# PROVISIONAL - NOT FOR LVS, TIMING SIGNOFF, FABRICATION OR TAPEOUT
# Synthetic pin placement derived from the Verilog header.
# North/south pins: met2 X grid 0.23 + N*0.46 um.
# West/east pins: met3 Y grid 0.34 + N*0.68 um.
# Analog pins: 1.30 um wide met3 access for matching-or-wider NDR.
# Supply pins: distributed met3 access copied from the released X1 GDS.
# OBS geometry: copied from the matching released X1 LEF.
VERSION 5.7 ;
BUSBITCHARS "[]" ;
DIVIDERCHAR "/" ;
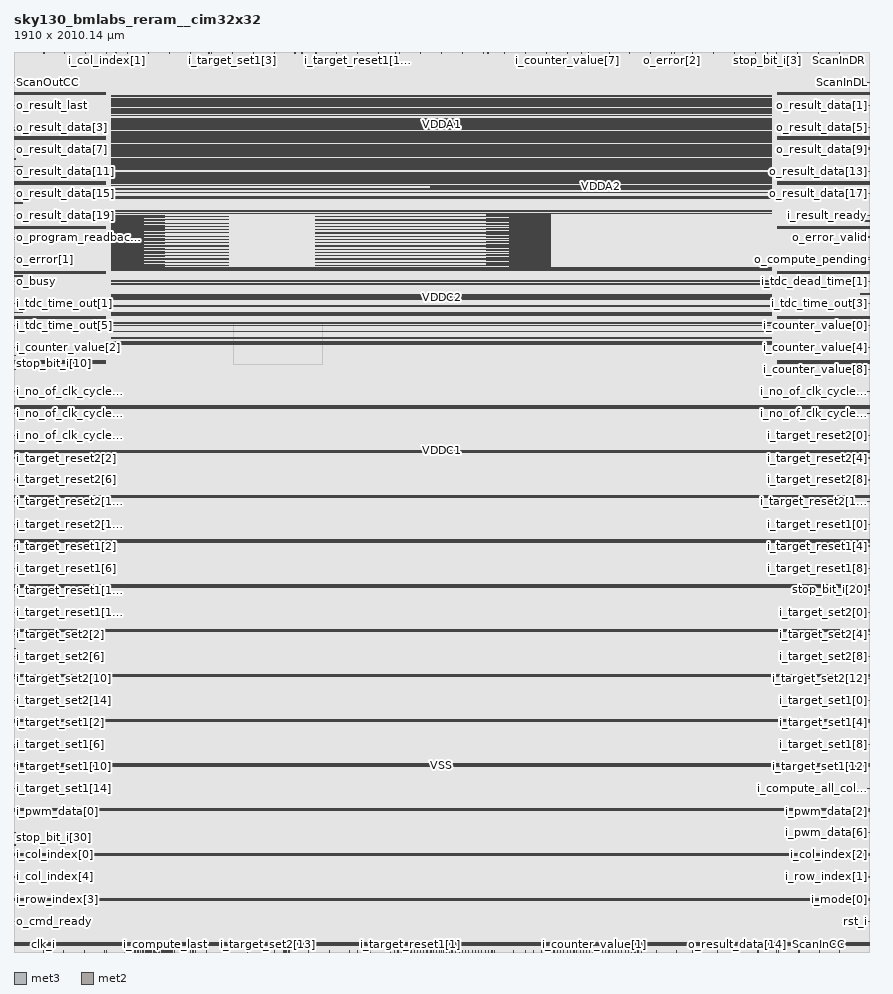
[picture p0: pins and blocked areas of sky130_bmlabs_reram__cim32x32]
MACRO sky130_bmlabs_reram__cim32x32
  CLASS BLOCK ;
  ORIGIN 0 0 ;
  FOREIGN sky130_bmlabs_reram__cim32x32 0 0 ;
  SIZE 1910 BY 2010.14 ;
  PIN VDDC1
    DIRECTION INOUT ;
    USE POWER ;
    PORT
      LAYER met3 ;
        RECT 1705 1318.6 1910 1320.4 ;
    END
    PORT
      LAYER met3 ;
        RECT 1705 1418.6 1910 1420.4 ;
    END
    PORT
      LAYER met3 ;
        RECT 1705 1518.6 1910 1520.4 ;
    END
    PORT
      LAYER met3 ;
        RECT 1705 1618.6 1910 1620.4 ;
    END
    PORT
      LAYER met3 ;
        RECT 1705 1718.6 1910 1720.4 ;
    END
    PORT
      LAYER met3 ;
        RECT 1705 1818.6 1910 1820.4 ;
    END
    PORT
      LAYER met3 ;
        RECT 1705 1918.6 1910 1920.4 ;
    END
    PORT
      LAYER met3 ;
        RECT 0 1718.6 205 1720.4 ;
    END
    PORT
      LAYER met3 ;
        RECT 0 1818.6 205 1820.4 ;
    END
    PORT
      LAYER met3 ;
        RECT 0 1918.6 205 1920.4 ;
    END
    PORT
      LAYER met3 ;
        RECT 0 1518.6 205 1520.4 ;
    END
    PORT
      LAYER met3 ;
        RECT 0 1618.6 205 1620.4 ;
    END
    PORT
      LAYER met3 ;
        RECT 0 1118.6 1910 1120.4 ;
    END
    PORT
      LAYER met3 ;
        RECT 0 1218.6 1910 1220.4 ;
    END
    PORT
      LAYER met3 ;
        RECT 0 1318.6 205 1320.4 ;
    END
    PORT
      LAYER met3 ;
        RECT 0 1018.6 1910 1020.4 ;
    END
    PORT
      LAYER met3 ;
        RECT 0 1418.6 205 1420.4 ;
    END
    PORT
      LAYER met3 ;
        RECT 0 718.6 1910 720.4 ;
    END
    PORT
      LAYER met3 ;
        RECT 0 818.6 1910 820.4 ;
    END
    PORT
      LAYER met3 ;
        RECT 0 418.6 1910 420.4 ;
    END
    PORT
      LAYER met3 ;
        RECT 0 918.6 1910 920.4 ;
    END
    PORT
      LAYER met3 ;
        RECT 0 318.6 1910 320.4 ;
    END
    PORT
      LAYER met3 ;
        RECT 0 18.6 1910 20.4 ;
    END
    PORT
      LAYER met3 ;
        RECT 0 118.6 1910 120.4 ;
    END
    PORT
      LAYER met3 ;
        RECT 0 218.6 1910 220.4 ;
    END
    PORT
      LAYER met3 ;
        RECT 0 518.6 1910 520.4 ;
    END
    PORT
      LAYER met3 ;
        RECT 0 618.6 1910 620.4 ;
    END
  END VDDC1
  PIN VDDC2
    DIRECTION INOUT ;
    USE POWER ;
    PORT
      LAYER met3 ;
        RECT 1107.355 1541.61 1198.805 1541.95 ;
    END
    PORT
      LAYER met3 ;
        RECT 1107.355 1538.89 1198.805 1539.23 ;
    END
    PORT
      LAYER met3 ;
        RECT 1107.355 1534.33 1198.805 1534.67 ;
    END
    PORT
      LAYER met3 ;
        RECT 1107.355 1531.61 1198.805 1531.95 ;
    END
    PORT
      LAYER met3 ;
        RECT 1107.355 1556.17 1198.805 1556.51 ;
    END
    PORT
      LAYER met3 ;
        RECT 1107.355 1553.45 1198.805 1553.79 ;
    END
    PORT
      LAYER met3 ;
        RECT 1107.355 1548.89 1198.805 1549.23 ;
    END
    PORT
      LAYER met3 ;
        RECT 1107.355 1546.17 1198.805 1546.51 ;
    END
    PORT
      LAYER met3 ;
        RECT 1107.355 1570.73 1198.805 1571.07 ;
    END
    PORT
      LAYER met3 ;
        RECT 1107.355 1568.01 1198.805 1568.35 ;
    END
    PORT
      LAYER met3 ;
        RECT 1107.355 1563.45 1198.805 1563.79 ;
    END
    PORT
      LAYER met3 ;
        RECT 1107.355 1560.73 1198.805 1561.07 ;
    END
    PORT
      LAYER met3 ;
        RECT 1107.355 1585.29 1198.805 1585.63 ;
    END
    PORT
      LAYER met3 ;
        RECT 1107.355 1582.57 1198.805 1582.91 ;
    END
    PORT
      LAYER met3 ;
        RECT 1107.355 1578.01 1198.805 1578.35 ;
    END
    PORT
      LAYER met3 ;
        RECT 1107.355 1575.29 1198.805 1575.63 ;
    END
    PORT
      LAYER met3 ;
        RECT 1107.355 1599.85 1198.805 1600.19 ;
    END
    PORT
      LAYER met3 ;
        RECT 1107.355 1597.13 1198.805 1597.47 ;
    END
    PORT
      LAYER met3 ;
        RECT 1107.355 1592.57 1198.805 1592.91 ;
    END
    PORT
      LAYER met3 ;
        RECT 1107.355 1589.85 1198.805 1590.19 ;
    END
    PORT
      LAYER met3 ;
        RECT 1107.355 1614.41 1198.805 1614.75 ;
    END
    PORT
      LAYER met3 ;
        RECT 1107.355 1611.69 1198.805 1612.03 ;
    END
    PORT
      LAYER met3 ;
        RECT 1107.355 1607.13 1198.805 1607.47 ;
    END
    PORT
      LAYER met3 ;
        RECT 1107.355 1604.41 1198.805 1604.75 ;
    END
    PORT
      LAYER met3 ;
        RECT 1107.355 1628.97 1198.805 1629.31 ;
    END
    PORT
      LAYER met3 ;
        RECT 1107.355 1626.25 1198.805 1626.59 ;
    END
    PORT
      LAYER met3 ;
        RECT 1107.355 1621.69 1198.805 1622.03 ;
    END
    PORT
      LAYER met3 ;
        RECT 1107.355 1618.97 1198.805 1619.31 ;
    END
    PORT
      LAYER met3 ;
        RECT 1107.355 1636.25 1198.805 1636.59 ;
    END
    PORT
      LAYER met3 ;
        RECT 1107.355 1640.81 1198.805 1641.15 ;
    END
    PORT
      LAYER met3 ;
        RECT 1107.355 1633.53 1198.805 1633.87 ;
    END
    PORT
      LAYER met3 ;
        RECT 1107.355 1643.53 1198.805 1643.87 ;
    END
    PORT
      LAYER met3 ;
        RECT 216.895 1905.7 1692.84 1906.7 ;
    END
    PORT
      LAYER met3 ;
        RECT 216.895 1903.7 1692.84 1904.7 ;
    END
    PORT
      LAYER met3 ;
        RECT 216.895 1899.7 1692.84 1900.7 ;
    END
    PORT
      LAYER met3 ;
        RECT 216.895 1910.255 1692.84 1911.255 ;
    END
    PORT
      LAYER met3 ;
        RECT 216.99 1639.315 288.37 1639.655 ;
    END
    PORT
      LAYER met3 ;
        RECT 216.99 1632.035 288.37 1632.375 ;
    END
    PORT
      LAYER met3 ;
        RECT 216.99 1551.955 288.37 1552.295 ;
    END
    PORT
      LAYER met3 ;
        RECT 216.99 1550.675 288.37 1551.015 ;
    END
    PORT
      LAYER met3 ;
        RECT 216.99 1543.395 288.37 1543.735 ;
    END
    PORT
      LAYER met3 ;
        RECT 216.99 1565.235 288.37 1565.575 ;
    END
    PORT
      LAYER met3 ;
        RECT 216.99 1587.075 288.37 1587.415 ;
    END
    PORT
      LAYER met3 ;
        RECT 216.99 1460.105 1692.935 1461.605 ;
    END
    PORT
      LAYER met3 ;
        RECT 216.99 1468.13 1692.935 1469.63 ;
    END
    PORT
      LAYER met3 ;
        RECT 216.99 1573.795 288.37 1574.135 ;
    END
    PORT
      LAYER met3 ;
        RECT 216.99 1581.075 288.37 1581.415 ;
    END
    PORT
      LAYER met3 ;
        RECT 216.99 1579.795 288.37 1580.135 ;
    END
    PORT
      LAYER met3 ;
        RECT 216.99 1530.115 288.37 1530.455 ;
    END
    PORT
      LAYER met3 ;
        RECT 216.99 1645.315 288.37 1645.655 ;
    END
    PORT
      LAYER met3 ;
        RECT 216.99 1463.105 1692.935 1464.605 ;
    END
    PORT
      LAYER met3 ;
        RECT 216.99 1523.695 1692.935 1524.695 ;
    END
    PORT
      LAYER met3 ;
        RECT 216.99 1537.395 288.37 1537.735 ;
    END
    PORT
      LAYER met3 ;
        RECT 216.99 1536.115 288.37 1536.455 ;
    END
    PORT
      LAYER met3 ;
        RECT 216.99 1557.955 288.37 1558.295 ;
    END
    PORT
      LAYER met3 ;
        RECT 216.99 1544.675 288.37 1545.015 ;
    END
    PORT
      LAYER met3 ;
        RECT 216.99 1601.635 288.37 1601.975 ;
    END
    PORT
      LAYER met3 ;
        RECT 216.99 1588.355 288.37 1588.695 ;
    END
    PORT
      LAYER met3 ;
        RECT 216.99 1595.635 288.37 1595.975 ;
    END
    PORT
      LAYER met3 ;
        RECT 216.99 1594.355 288.37 1594.695 ;
    END
    PORT
      LAYER met3 ;
        RECT 216.99 1616.195 288.37 1616.535 ;
    END
    PORT
      LAYER met3 ;
        RECT 216.99 1602.915 288.37 1603.255 ;
    END
    PORT
      LAYER met3 ;
        RECT 216.99 1610.195 288.37 1610.535 ;
    END
    PORT
      LAYER met3 ;
        RECT 216.99 1608.915 288.37 1609.255 ;
    END
    PORT
      LAYER met3 ;
        RECT 216.99 1630.755 288.37 1631.095 ;
    END
    PORT
      LAYER met3 ;
        RECT 216.99 1617.475 288.37 1617.815 ;
    END
    PORT
      LAYER met3 ;
        RECT 216.99 1624.755 288.37 1625.095 ;
    END
    PORT
      LAYER met3 ;
        RECT 216.99 1559.235 288.37 1559.575 ;
    END
    PORT
      LAYER met3 ;
        RECT 216.99 1623.475 288.37 1623.815 ;
    END
    PORT
      LAYER met3 ;
        RECT 216.99 1638.035 288.37 1638.375 ;
    END
    PORT
      LAYER met3 ;
        RECT 216.99 1572.515 288.37 1572.855 ;
    END
    PORT
      LAYER met3 ;
        RECT 216.99 1566.515 288.37 1566.855 ;
    END
    PORT
      LAYER met3 ;
        RECT 216.99 1398.62 1692.935 1399.62 ;
    END
    PORT
      LAYER met3 ;
        RECT 216.99 1385.695 1692.935 1386.695 ;
    END
    PORT
      LAYER met3 ;
        RECT 216.99 1362.35 1692.935 1363.85 ;
    END
    PORT
      LAYER met3 ;
        RECT 216.99 1404.27 1692.935 1405.27 ;
    END
    PORT
      LAYER met3 ;
        RECT 216.99 1426.895 1692.935 1428.395 ;
    END
    PORT
      LAYER met3 ;
        RECT 216.99 1424.145 1692.935 1425.645 ;
    END
  END VDDC2
  PIN VDDA1
    DIRECTION INOUT ;
    USE POWER ;
    PORT
      LAYER met3 ;
        RECT 1056.405 1529.33 1198.805 1529.67 ;
    END
    PORT
      LAYER met3 ;
        RECT 1056.405 1536.61 1198.805 1536.95 ;
    END
    PORT
      LAYER met3 ;
        RECT 1056.405 1543.89 1198.805 1544.23 ;
    END
    PORT
      LAYER met3 ;
        RECT 1056.405 1551.17 1198.805 1551.51 ;
    END
    PORT
      LAYER met3 ;
        RECT 1056.405 1558.45 1198.805 1558.79 ;
    END
    PORT
      LAYER met3 ;
        RECT 1056.405 1565.73 1198.805 1566.07 ;
    END
    PORT
      LAYER met3 ;
        RECT 1056.405 1573.01 1198.805 1573.35 ;
    END
    PORT
      LAYER met3 ;
        RECT 1056.405 1580.29 1198.805 1580.63 ;
    END
    PORT
      LAYER met3 ;
        RECT 1056.405 1587.57 1198.805 1587.91 ;
    END
    PORT
      LAYER met3 ;
        RECT 1056.405 1594.85 1198.805 1595.19 ;
    END
    PORT
      LAYER met3 ;
        RECT 1056.405 1602.13 1198.805 1602.47 ;
    END
    PORT
      LAYER met3 ;
        RECT 1056.405 1609.41 1198.805 1609.75 ;
    END
    PORT
      LAYER met3 ;
        RECT 1056.405 1616.69 1198.805 1617.03 ;
    END
    PORT
      LAYER met3 ;
        RECT 1056.405 1623.97 1198.805 1624.31 ;
    END
    PORT
      LAYER met3 ;
        RECT 1056.405 1638.53 1198.805 1638.87 ;
    END
    PORT
      LAYER met3 ;
        RECT 1056.405 1631.25 1198.805 1631.59 ;
    END
    PORT
      LAYER met3 ;
        RECT 1056.405 1645.81 1198.805 1646.15 ;
    END
    PORT
      LAYER met3 ;
        RECT 216.895 1848.475 1692.84 1849.475 ;
    END
    PORT
      LAYER met3 ;
        RECT 216.895 1812.94 1692.84 1813.94 ;
    END
    PORT
      LAYER met3 ;
        RECT 216.895 1783.685 1692.84 1784.685 ;
    END
    PORT
      LAYER met3 ;
        RECT 216.895 1755.265 1692.84 1756.265 ;
    END
    PORT
      LAYER met3 ;
        RECT 216.895 1723 1692.84 1724 ;
    END
    PORT
      LAYER met3 ;
        RECT 216.895 1729 1692.84 1730 ;
    END
    PORT
      LAYER met3 ;
        RECT 216.895 1703.22 1692.84 1704.22 ;
    END
    PORT
      LAYER met3 ;
        RECT 216.895 1695.22 1692.84 1696.22 ;
    END
    PORT
      LAYER met3 ;
        RECT 216.895 1687.22 1692.84 1688.22 ;
    END
    PORT
      LAYER met3 ;
        RECT 216.895 1872.1 1692.84 1873.1 ;
    END
    PORT
      LAYER met3 ;
        RECT 216.895 1874.1 1692.84 1875.1 ;
    END
    PORT
      LAYER met3 ;
        RECT 216.895 1876.1 1692.84 1877.1 ;
    END
    PORT
      LAYER met3 ;
        RECT 216.895 1878.1 1692.84 1879.1 ;
    END
    PORT
      LAYER met3 ;
        RECT 216.895 1880.1 1692.84 1881.1 ;
    END
    PORT
      LAYER met3 ;
        RECT 216.895 1711.22 1692.84 1712.22 ;
    END
    PORT
      LAYER met3 ;
        RECT 216.895 1735 1692.84 1736 ;
    END
    PORT
      LAYER met3 ;
        RECT 216.895 1741 1692.84 1742 ;
    END
    PORT
      LAYER met3 ;
        RECT 216.895 1767.265 1692.84 1768.265 ;
    END
    PORT
      LAYER met3 ;
        RECT 216.895 1795.685 1692.84 1796.685 ;
    END
    PORT
      LAYER met3 ;
        RECT 216.895 1824.94 1692.84 1825.94 ;
    END
    PORT
      LAYER met3 ;
        RECT 216.895 1685.36 1692.84 1686.36 ;
    END
    PORT
      LAYER met3 ;
        RECT 216.895 1860.475 1692.84 1861.475 ;
    END
    PORT
      LAYER met3 ;
        RECT 216.895 1882.1 1692.84 1883.1 ;
    END
    PORT
      LAYER met3 ;
        RECT 216.99 1633.675 336.095 1634.015 ;
    END
    PORT
      LAYER met3 ;
        RECT 216.99 1553.595 336.095 1553.935 ;
    END
    PORT
      LAYER met3 ;
        RECT 216.99 1549.035 336.095 1549.375 ;
    END
    PORT
      LAYER met3 ;
        RECT 216.99 1556.315 336.095 1556.655 ;
    END
    PORT
      LAYER met3 ;
        RECT 216.99 1570.875 336.095 1571.215 ;
    END
    PORT
      LAYER met3 ;
        RECT 216.99 1643.675 336.095 1644.015 ;
    END
    PORT
      LAYER met3 ;
        RECT 216.99 1575.435 336.095 1575.775 ;
    END
    PORT
      LAYER met3 ;
        RECT 216.99 1582.715 336.095 1583.055 ;
    END
    PORT
      LAYER met3 ;
        RECT 216.99 1525.295 1692.935 1526.295 ;
    END
    PORT
      LAYER met3 ;
        RECT 216.895 1653.885 1692.84 1654.885 ;
    END
    PORT
      LAYER met3 ;
        RECT 216.99 1578.155 336.095 1578.495 ;
    END
    PORT
      LAYER met3 ;
        RECT 216.99 1585.435 336.095 1585.775 ;
    END
    PORT
      LAYER met3 ;
        RECT 216.99 1531.755 336.095 1532.095 ;
    END
    PORT
      LAYER met3 ;
        RECT 216.99 1539.035 336.095 1539.375 ;
    END
    PORT
      LAYER met3 ;
        RECT 216.99 1534.475 336.095 1534.815 ;
    END
    PORT
      LAYER met3 ;
        RECT 216.99 1541.755 336.095 1542.095 ;
    END
    PORT
      LAYER met3 ;
        RECT 216.99 1546.315 336.095 1546.655 ;
    END
    PORT
      LAYER met3 ;
        RECT 216.99 1589.995 336.095 1590.335 ;
    END
    PORT
      LAYER met3 ;
        RECT 216.99 1597.275 336.095 1597.615 ;
    END
    PORT
      LAYER met3 ;
        RECT 216.99 1592.715 336.095 1593.055 ;
    END
    PORT
      LAYER met3 ;
        RECT 216.99 1599.995 336.095 1600.335 ;
    END
    PORT
      LAYER met3 ;
        RECT 216.99 1604.555 336.095 1604.895 ;
    END
    PORT
      LAYER met3 ;
        RECT 216.99 1611.835 336.095 1612.175 ;
    END
    PORT
      LAYER met3 ;
        RECT 216.99 1607.275 336.095 1607.615 ;
    END
    PORT
      LAYER met3 ;
        RECT 216.99 1614.555 336.095 1614.895 ;
    END
    PORT
      LAYER met3 ;
        RECT 216.99 1619.115 336.095 1619.455 ;
    END
    PORT
      LAYER met3 ;
        RECT 216.99 1626.395 336.095 1626.735 ;
    END
    PORT
      LAYER met3 ;
        RECT 216.99 1621.835 336.095 1622.175 ;
    END
    PORT
      LAYER met3 ;
        RECT 216.99 1629.115 336.095 1629.455 ;
    END
    PORT
      LAYER met3 ;
        RECT 216.99 1560.875 336.095 1561.215 ;
    END
    PORT
      LAYER met3 ;
        RECT 216.99 1636.395 336.095 1636.735 ;
    END
    PORT
      LAYER met3 ;
        RECT 216.99 1640.955 336.095 1641.295 ;
    END
    PORT
      LAYER met3 ;
        RECT 216.99 1568.155 336.095 1568.495 ;
    END
    PORT
      LAYER met3 ;
        RECT 216.99 1563.595 336.095 1563.935 ;
    END
  END VDDA1
  PIN VDDA2
    DIRECTION INOUT ;
    USE POWER ;
    PORT
      LAYER met3 ;
        RECT 929.635 1709.36 1692.84 1710.36 ;
    END
    PORT
      LAYER met3 ;
        RECT 929.635 1707.36 1692.84 1708.36 ;
    END
    PORT
      LAYER met3 ;
        RECT 929.635 1705.36 1692.84 1706.36 ;
    END
  END VDDA2
  PIN VSS
    DIRECTION INOUT ;
    USE GROUND ;
    PORT
      LAYER met3 ;
        RECT 673.905 1532.97 1198.805 1533.31 ;
    END
    PORT
      LAYER met3 ;
        RECT 673.905 1540.25 1198.805 1540.59 ;
    END
    PORT
      LAYER met3 ;
        RECT 673.905 1547.53 1198.805 1547.87 ;
    END
    PORT
      LAYER met3 ;
        RECT 673.905 1554.81 1198.805 1555.15 ;
    END
    PORT
      LAYER met3 ;
        RECT 673.905 1562.09 1198.805 1562.43 ;
    END
    PORT
      LAYER met3 ;
        RECT 673.905 1569.37 1198.805 1569.71 ;
    END
    PORT
      LAYER met3 ;
        RECT 673.905 1576.65 1198.805 1576.99 ;
    END
    PORT
      LAYER met3 ;
        RECT 673.905 1583.93 1198.805 1584.27 ;
    END
    PORT
      LAYER met3 ;
        RECT 673.905 1591.21 1198.805 1591.55 ;
    END
    PORT
      LAYER met3 ;
        RECT 673.905 1598.49 1198.805 1598.83 ;
    END
    PORT
      LAYER met3 ;
        RECT 673.905 1605.77 1198.805 1606.11 ;
    END
    PORT
      LAYER met3 ;
        RECT 673.905 1613.05 1198.805 1613.39 ;
    END
    PORT
      LAYER met3 ;
        RECT 673.905 1620.33 1198.805 1620.67 ;
    END
    PORT
      LAYER met3 ;
        RECT 673.905 1627.61 1198.805 1627.95 ;
    END
    PORT
      LAYER met3 ;
        RECT 673.905 1634.89 1198.805 1635.23 ;
    END
    PORT
      LAYER met3 ;
        RECT 673.905 1642.17 1198.805 1642.51 ;
    END
    PORT
      LAYER met3 ;
        RECT 1705 1315 1910 1316.8 ;
    END
    PORT
      LAYER met3 ;
        RECT 1705 1415 1910 1416.8 ;
    END
    PORT
      LAYER met3 ;
        RECT 1705 1515 1910 1516.8 ;
    END
    PORT
      LAYER met3 ;
        RECT 1705 1615 1910 1616.8 ;
    END
    PORT
      LAYER met3 ;
        RECT 1705 1715 1910 1716.8 ;
    END
    PORT
      LAYER met3 ;
        RECT 1705 1815 1910 1816.8 ;
    END
    PORT
      LAYER met3 ;
        RECT 1705 1915 1910 1916.8 ;
    END
    PORT
      LAYER met3 ;
        RECT 216.895 1838.475 1692.84 1839.475 ;
    END
    PORT
      LAYER met3 ;
        RECT 216.895 1840.475 1692.84 1841.475 ;
    END
    PORT
      LAYER met3 ;
        RECT 216.895 1842.475 1692.84 1843.475 ;
    END
    PORT
      LAYER met3 ;
        RECT 216.895 1844.475 1692.84 1845.475 ;
    END
    PORT
      LAYER met3 ;
        RECT 216.895 1846.475 1692.84 1847.475 ;
    END
    PORT
      LAYER met3 ;
        RECT 216.895 1836.475 1692.84 1837.475 ;
    END
    PORT
      LAYER met3 ;
        RECT 216.895 1808.94 1692.84 1809.94 ;
    END
    PORT
      LAYER met3 ;
        RECT 216.895 1810.94 1692.84 1811.94 ;
    END
    PORT
      LAYER met3 ;
        RECT 216.895 1814.94 1692.84 1815.94 ;
    END
    PORT
      LAYER met3 ;
        RECT 216.895 1816.94 1692.84 1817.94 ;
    END
    PORT
      LAYER met3 ;
        RECT 216.895 1818.94 1692.84 1819.94 ;
    END
    PORT
      LAYER met3 ;
        RECT 216.895 1806.94 1692.84 1807.94 ;
    END
    PORT
      LAYER met3 ;
        RECT 216.895 1779.685 1692.84 1780.685 ;
    END
    PORT
      LAYER met3 ;
        RECT 216.895 1781.685 1692.84 1782.685 ;
    END
    PORT
      LAYER met3 ;
        RECT 216.895 1785.685 1692.84 1786.685 ;
    END
    PORT
      LAYER met3 ;
        RECT 216.895 1787.685 1692.84 1788.685 ;
    END
    PORT
      LAYER met3 ;
        RECT 216.895 1789.685 1692.84 1790.685 ;
    END
    PORT
      LAYER met3 ;
        RECT 216.895 1777.685 1692.84 1778.685 ;
    END
    PORT
      LAYER met3 ;
        RECT 216.895 1749.265 1692.84 1750.265 ;
    END
    PORT
      LAYER met3 ;
        RECT 216.895 1751.265 1692.84 1752.265 ;
    END
    PORT
      LAYER met3 ;
        RECT 216.895 1753.265 1692.84 1754.265 ;
    END
    PORT
      LAYER met3 ;
        RECT 216.895 1757.265 1692.84 1758.265 ;
    END
    PORT
      LAYER met3 ;
        RECT 216.895 1759.265 1692.84 1760.265 ;
    END
    PORT
      LAYER met3 ;
        RECT 216.895 1747.265 1692.84 1748.265 ;
    END
    PORT
      LAYER met3 ;
        RECT 216.895 1719 1692.84 1720 ;
    END
    PORT
      LAYER met3 ;
        RECT 216.895 1721 1692.84 1722 ;
    END
    PORT
      LAYER met3 ;
        RECT 216.895 1725 1692.84 1726 ;
    END
    PORT
      LAYER met3 ;
        RECT 216.895 1727 1692.84 1728 ;
    END
    PORT
      LAYER met3 ;
        RECT 216.895 1717 1692.84 1718 ;
    END
    PORT
      LAYER met3 ;
        RECT 216.895 1683.5 1692.84 1684.5 ;
    END
    PORT
      LAYER met3 ;
        RECT 216.895 1912.515 1692.84 1913.515 ;
    END
    PORT
      LAYER met3 ;
        RECT 216.895 1737 1692.84 1738 ;
    END
    PORT
      LAYER met3 ;
        RECT 216.895 1739 1692.84 1740 ;
    END
    PORT
      LAYER met3 ;
        RECT 216.895 1731 1692.84 1732 ;
    END
    PORT
      LAYER met3 ;
        RECT 216.895 1733 1692.84 1734 ;
    END
    PORT
      LAYER met3 ;
        RECT 216.895 1761.265 1692.84 1762.265 ;
    END
    PORT
      LAYER met3 ;
        RECT 216.895 1763.265 1692.84 1764.265 ;
    END
    PORT
      LAYER met3 ;
        RECT 216.895 1765.265 1692.84 1766.265 ;
    END
    PORT
      LAYER met3 ;
        RECT 216.895 1769.265 1692.84 1770.265 ;
    END
    PORT
      LAYER met3 ;
        RECT 216.895 1771.265 1692.84 1772.265 ;
    END
    PORT
      LAYER met3 ;
        RECT 216.895 1791.685 1692.84 1792.685 ;
    END
    PORT
      LAYER met3 ;
        RECT 216.895 1793.685 1692.84 1794.685 ;
    END
    PORT
      LAYER met3 ;
        RECT 216.895 1797.685 1692.84 1798.685 ;
    END
    PORT
      LAYER met3 ;
        RECT 216.895 1799.685 1692.84 1800.685 ;
    END
    PORT
      LAYER met3 ;
        RECT 216.895 1801.685 1692.84 1802.685 ;
    END
    PORT
      LAYER met3 ;
        RECT 216.895 1820.94 1692.84 1821.94 ;
    END
    PORT
      LAYER met3 ;
        RECT 216.895 1822.94 1692.84 1823.94 ;
    END
    PORT
      LAYER met3 ;
        RECT 216.895 1826.94 1692.84 1827.94 ;
    END
    PORT
      LAYER met3 ;
        RECT 216.895 1828.94 1692.84 1829.94 ;
    END
    PORT
      LAYER met3 ;
        RECT 216.895 1830.94 1692.84 1831.94 ;
    END
    PORT
      LAYER met3 ;
        RECT 216.895 1850.475 1692.84 1851.475 ;
    END
    PORT
      LAYER met3 ;
        RECT 216.895 1852.475 1692.84 1853.475 ;
    END
    PORT
      LAYER met3 ;
        RECT 216.895 1854.475 1692.84 1855.475 ;
    END
    PORT
      LAYER met3 ;
        RECT 216.895 1856.475 1692.84 1857.475 ;
    END
    PORT
      LAYER met3 ;
        RECT 216.895 1858.475 1692.84 1859.475 ;
    END
    PORT
      LAYER met3 ;
        RECT 216.895 1868.02 1692.84 1869.02 ;
    END
    PORT
      LAYER met3 ;
        RECT 216.895 1887.335 1692.84 1888.335 ;
    END
    PORT
      LAYER met3 ;
        RECT 216.895 1889.335 1692.84 1890.335 ;
    END
    PORT
      LAYER met3 ;
        RECT 216.895 1891.335 1692.84 1892.335 ;
    END
    PORT
      LAYER met3 ;
        RECT 216.895 1893.335 1692.84 1894.335 ;
    END
    PORT
      LAYER met3 ;
        RECT 216.895 1897.7 1692.84 1898.7 ;
    END
    PORT
      LAYER met3 ;
        RECT 216.895 1901.7 1692.84 1902.7 ;
    END
    PORT
      LAYER met3 ;
        RECT 0 1915 205 1916.8 ;
    END
    PORT
      LAYER met3 ;
        RECT 0 1715 205 1716.8 ;
    END
    PORT
      LAYER met3 ;
        RECT 0 1815 205 1816.8 ;
    END
    PORT
      LAYER met3 ;
        RECT 0 1515 205 1516.8 ;
    END
    PORT
      LAYER met3 ;
        RECT 0 1615 205 1616.8 ;
    END
    PORT
      LAYER met3 ;
        RECT 216.99 1635.035 478.585 1635.375 ;
    END
    PORT
      LAYER met3 ;
        RECT 216.99 1547.675 478.585 1548.015 ;
    END
    PORT
      LAYER met3 ;
        RECT 216.99 1540.395 478.585 1540.735 ;
    END
    PORT
      LAYER met3 ;
        RECT 216.99 1584.075 478.585 1584.415 ;
    END
    PORT
      LAYER met3 ;
        RECT 216.99 1465.725 1692.935 1467.225 ;
    END
    PORT
      LAYER met3 ;
        RECT 216.99 1576.795 478.585 1577.135 ;
    END
    PORT
      LAYER met3 ;
        RECT 216.99 1649.175 1692.935 1650.175 ;
    END
    PORT
      LAYER met3 ;
        RECT 216.99 1526.75 1692.935 1527.75 ;
    END
    PORT
      LAYER met3 ;
        RECT 216.99 1598.635 478.585 1598.975 ;
    END
    PORT
      LAYER met3 ;
        RECT 216.99 1457.28 1692.935 1458.78 ;
    END
    PORT
      LAYER met3 ;
        RECT 216.99 1642.315 478.585 1642.655 ;
    END
    PORT
      LAYER met3 ;
        RECT 216.99 1533.115 478.585 1533.455 ;
    END
    PORT
      LAYER met3 ;
        RECT 216.99 1490.735 1692.935 1492.235 ;
    END
    PORT
      LAYER met3 ;
        RECT 216.99 1497.995 1692.935 1499.495 ;
    END
    PORT
      LAYER met3 ;
        RECT 216.99 1521.18 1692.935 1522.18 ;
    END
    PORT
      LAYER met3 ;
        RECT 216.895 1655.425 1692.84 1656.425 ;
    END
    PORT
      LAYER met3 ;
        RECT 216.99 1554.955 478.585 1555.295 ;
    END
    PORT
      LAYER met3 ;
        RECT 216.99 1591.355 478.585 1591.695 ;
    END
    PORT
      LAYER met3 ;
        RECT 216.99 1613.195 478.585 1613.535 ;
    END
    PORT
      LAYER met3 ;
        RECT 216.99 1605.915 478.585 1606.255 ;
    END
    PORT
      LAYER met3 ;
        RECT 216.99 1627.755 478.585 1628.095 ;
    END
    PORT
      LAYER met3 ;
        RECT 216.99 1620.475 478.585 1620.815 ;
    END
    PORT
      LAYER met3 ;
        RECT 216.99 1562.235 478.585 1562.575 ;
    END
    PORT
      LAYER met3 ;
        RECT 216.99 1569.515 478.585 1569.855 ;
    END
    PORT
      LAYER met3 ;
        RECT 0 1415 205 1416.8 ;
    END
    PORT
      LAYER met3 ;
        RECT 216.99 1441.55 1692.935 1443.05 ;
    END
    PORT
      LAYER met3 ;
        RECT 0 1115 1910 1116.8 ;
    END
    PORT
      LAYER met3 ;
        RECT 0 1215 1910 1216.8 ;
    END
    PORT
      LAYER met3 ;
        RECT 216.99 1357.08 1692.935 1358.58 ;
    END
    PORT
      LAYER met3 ;
        RECT 216.99 1371.215 1692.935 1372.715 ;
    END
    PORT
      LAYER met3 ;
        RECT 0 1315 205 1316.8 ;
    END
    PORT
      LAYER met3 ;
        RECT 0 1015 1910 1016.8 ;
    END
    PORT
      LAYER met3 ;
        RECT 216.99 1421.265 1692.935 1422.765 ;
    END
    PORT
      LAYER met3 ;
        RECT 0 715 1910 716.8 ;
    END
    PORT
      LAYER met3 ;
        RECT 0 815 1910 816.8 ;
    END
    PORT
      LAYER met3 ;
        RECT 0 415 1910 416.8 ;
    END
    PORT
      LAYER met3 ;
        RECT 0 915 1910 916.8 ;
    END
    PORT
      LAYER met3 ;
        RECT 0 315 1910 316.8 ;
    END
    PORT
      LAYER met3 ;
        RECT 0 15 1910 16.8 ;
    END
    PORT
      LAYER met3 ;
        RECT 0 115 1910 116.8 ;
    END
    PORT
      LAYER met3 ;
        RECT 0 215 1910 216.8 ;
    END
    PORT
      LAYER met3 ;
        RECT 0 515 1910 516.8 ;
    END
    PORT
      LAYER met3 ;
        RECT 0 615 1910 616.8 ;
    END
  END VSS
  PIN interface_sel
    DIRECTION INPUT ;
    USE SIGNAL ;
    PORT
      LAYER met2 ;
        RECT 207.08 0 207.38 2.91 ;
    END
  END interface_sel
  PIN i_Levelsh_enable
    DIRECTION INPUT ;
    USE SIGNAL ;
    PORT
      LAYER met3 ;
        RECT 1907.09 217.79 1910 218.09 ;
    END
  END i_Levelsh_enable
  PIN clk_i
    DIRECTION INPUT ;
    USE SIGNAL ;
    PORT
      LAYER met2 ;
        RECT 65.4 0 65.7 2.91 ;
    END
  END clk_i
  PIN rst_i
    DIRECTION INPUT ;
    USE SIGNAL ;
    PORT
      LAYER met3 ;
        RECT 1907.09 68.87 1910 69.17 ;
    END
  END rst_i
  PIN i_cmd_valid
    DIRECTION INPUT ;
    USE SIGNAL ;
    PORT
      LAYER met2 ;
        RECT 66.78 2007.23 67.08 2010.14 ;
    END
  END i_cmd_valid
  PIN o_cmd_ready
    DIRECTION OUTPUT ;
    USE SIGNAL ;
    PORT
      LAYER met3 ;
        RECT 0 68.87 2.91 69.17 ;
    END
  END o_cmd_ready
  PIN i_mode[1]
    DIRECTION INPUT ;
    USE SIGNAL ;
    PORT
      LAYER met2 ;
        RECT 110.94 0 111.24 2.91 ;
    END
  END i_mode[1]
  PIN i_mode[0]
    DIRECTION INPUT ;
    USE SIGNAL ;
    PORT
      LAYER met3 ;
        RECT 1907.09 117.83 1910 118.13 ;
    END
  END i_mode[0]
  PIN i_row_index[4]
    DIRECTION INPUT ;
    USE SIGNAL ;
    PORT
      LAYER met2 ;
        RECT 113.24 2007.23 113.54 2010.14 ;
    END
  END i_row_index[4]
  PIN i_row_index[3]
    DIRECTION INPUT ;
    USE SIGNAL ;
    PORT
      LAYER met3 ;
        RECT 0 117.83 2.91 118.13 ;
    END
  END i_row_index[3]
  PIN i_row_index[2]
    DIRECTION INPUT ;
    USE SIGNAL ;
    PORT
      LAYER met2 ;
        RECT 156.48 0 156.78 2.91 ;
    END
  END i_row_index[2]
  PIN i_row_index[1]
    DIRECTION INPUT ;
    USE SIGNAL ;
    PORT
      LAYER met3 ;
        RECT 1907.09 167.47 1910 167.77 ;
    END
  END i_row_index[1]
  PIN i_row_index[0]
    DIRECTION INPUT ;
    USE SIGNAL ;
    PORT
      LAYER met2 ;
        RECT 160.16 2007.23 160.46 2010.14 ;
    END
  END i_row_index[0]
  PIN i_col_index[4]
    DIRECTION INPUT ;
    USE SIGNAL ;
    PORT
      LAYER met3 ;
        RECT 0 167.47 2.91 167.77 ;
    END
  END i_col_index[4]
  PIN i_col_index[3]
    DIRECTION INPUT ;
    USE SIGNAL ;
    PORT
      LAYER met2 ;
        RECT 202.48 0 202.78 2.91 ;
    END
  END i_col_index[3]
  PIN i_col_index[2]
    DIRECTION INPUT ;
    USE SIGNAL ;
    PORT
      LAYER met3 ;
        RECT 1907.09 217.11 1910 217.41 ;
    END
  END i_col_index[2]
  PIN i_col_index[1]
    DIRECTION INPUT ;
    USE SIGNAL ;
    PORT
      LAYER met2 ;
        RECT 207.08 2007.23 207.38 2010.14 ;
    END
  END i_col_index[1]
  PIN i_col_index[0]
    DIRECTION INPUT ;
    USE SIGNAL ;
    PORT
      LAYER met3 ;
        RECT 0 217.11 2.91 217.41 ;
    END
  END i_col_index[0]
  PIN i_pwm_data[7]
    DIRECTION INPUT ;
    USE SIGNAL ;
    PORT
      LAYER met2 ;
        RECT 248.02 0 248.32 2.91 ;
    END
  END i_pwm_data[7]
  PIN i_pwm_data[6]
    DIRECTION INPUT ;
    USE SIGNAL ;
    PORT
      LAYER met3 ;
        RECT 1907.09 266.07 1910 266.37 ;
    END
  END i_pwm_data[6]
  PIN i_pwm_data[5]
    DIRECTION INPUT ;
    USE SIGNAL ;
    PORT
      LAYER met2 ;
        RECT 253.54 2007.23 253.84 2010.14 ;
    END
  END i_pwm_data[5]
  PIN i_pwm_data[4]
    DIRECTION INPUT ;
    USE SIGNAL ;
    PORT
      LAYER met3 ;
        RECT 0 266.07 2.91 266.37 ;
    END
  END i_pwm_data[4]
  PIN i_pwm_data[3]
    DIRECTION INPUT ;
    USE SIGNAL ;
    PORT
      LAYER met2 ;
        RECT 293.56 0 293.86 2.91 ;
    END
  END i_pwm_data[3]
  PIN i_pwm_data[2]
    DIRECTION INPUT ;
    USE SIGNAL ;
    PORT
      LAYER met3 ;
        RECT 1907.09 314.35 1910 314.65 ;
    END
  END i_pwm_data[2]
  PIN i_pwm_data[1]
    DIRECTION INPUT ;
    USE SIGNAL ;
    PORT
      LAYER met2 ;
        RECT 300.46 2007.23 300.76 2010.14 ;
    END
  END i_pwm_data[1]
  PIN i_pwm_data[0]
    DIRECTION INPUT ;
    USE SIGNAL ;
    PORT
      LAYER met3 ;
        RECT 0 314.35 2.91 314.65 ;
    END
  END i_pwm_data[0]
  PIN i_compute_last
    DIRECTION INPUT ;
    USE SIGNAL ;
    PORT
      LAYER met2 ;
        RECT 339.1 0 339.4 2.91 ;
    END
  END i_compute_last
  PIN i_compute_all_columns
    DIRECTION INPUT ;
    USE SIGNAL ;
    PORT
      LAYER met3 ;
        RECT 1907.09 364.67 1910 364.97 ;
    END
  END i_compute_all_columns
  PIN i_target_set1[15]
    DIRECTION INPUT ;
    USE SIGNAL ;
    PORT
      LAYER met2 ;
        RECT 346.92 2007.23 347.22 2010.14 ;
    END
  END i_target_set1[15]
  PIN i_target_set1[14]
    DIRECTION INPUT ;
    USE SIGNAL ;
    PORT
      LAYER met3 ;
        RECT 0 364.67 2.91 364.97 ;
    END
  END i_target_set1[14]
  PIN i_target_set1[13]
    DIRECTION INPUT ;
    USE SIGNAL ;
    PORT
      LAYER met2 ;
        RECT 384.64 0 384.94 2.91 ;
    END
  END i_target_set1[13]
  PIN i_target_set1[12]
    DIRECTION INPUT ;
    USE SIGNAL ;
    PORT
      LAYER met3 ;
        RECT 1907.09 413.63 1910 413.93 ;
    END
  END i_target_set1[12]
  PIN i_target_set1[11]
    DIRECTION INPUT ;
    USE SIGNAL ;
    PORT
      LAYER met2 ;
        RECT 393.84 2007.23 394.14 2010.14 ;
    END
  END i_target_set1[11]
  PIN i_target_set1[10]
    DIRECTION INPUT ;
    USE SIGNAL ;
    PORT
      LAYER met3 ;
        RECT 0 413.63 2.91 413.93 ;
    END
  END i_target_set1[10]
  PIN i_target_set1[9]
    DIRECTION INPUT ;
    USE SIGNAL ;
    PORT
      LAYER met2 ;
        RECT 430.18 0 430.48 2.91 ;
    END
  END i_target_set1[9]
  PIN i_target_set1[8]
    DIRECTION INPUT ;
    USE SIGNAL ;
    PORT
      LAYER met3 ;
        RECT 1907.09 463.27 1910 463.57 ;
    END
  END i_target_set1[8]
  PIN i_target_set1[7]
    DIRECTION INPUT ;
    USE SIGNAL ;
    PORT
      LAYER met2 ;
        RECT 440.76 2007.23 441.06 2010.14 ;
    END
  END i_target_set1[7]
  PIN i_target_set1[6]
    DIRECTION INPUT ;
    USE SIGNAL ;
    PORT
      LAYER met3 ;
        RECT 0 463.27 2.91 463.57 ;
    END
  END i_target_set1[6]
  PIN i_target_set1[5]
    DIRECTION INPUT ;
    USE SIGNAL ;
    PORT
      LAYER met2 ;
        RECT 475.72 0 476.02 2.91 ;
    END
  END i_target_set1[5]
  PIN i_target_set1[4]
    DIRECTION INPUT ;
    USE SIGNAL ;
    PORT
      LAYER met3 ;
        RECT 1907.09 512.23 1910 512.53 ;
    END
  END i_target_set1[4]
  PIN i_target_set1[3]
    DIRECTION INPUT ;
    USE SIGNAL ;
    PORT
      LAYER met2 ;
        RECT 487.22 2007.23 487.52 2010.14 ;
    END
  END i_target_set1[3]
  PIN i_target_set1[2]
    DIRECTION INPUT ;
    USE SIGNAL ;
    PORT
      LAYER met3 ;
        RECT 0 512.23 2.91 512.53 ;
    END
  END i_target_set1[2]
  PIN i_target_set1[1]
    DIRECTION INPUT ;
    USE SIGNAL ;
    PORT
      LAYER met2 ;
        RECT 521.72 0 522.02 2.91 ;
    END
  END i_target_set1[1]
  PIN i_target_set1[0]
    DIRECTION INPUT ;
    USE SIGNAL ;
    PORT
      LAYER met3 ;
        RECT 1907.09 561.87 1910 562.17 ;
    END
  END i_target_set1[0]
  PIN i_target_set2[15]
    DIRECTION INPUT ;
    USE SIGNAL ;
    PORT
      LAYER met2 ;
        RECT 534.14 2007.23 534.44 2010.14 ;
    END
  END i_target_set2[15]
  PIN i_target_set2[14]
    DIRECTION INPUT ;
    USE SIGNAL ;
    PORT
      LAYER met3 ;
        RECT 0 561.87 2.91 562.17 ;
    END
  END i_target_set2[14]
  PIN i_target_set2[13]
    DIRECTION INPUT ;
    USE SIGNAL ;
    PORT
      LAYER met2 ;
        RECT 567.26 0 567.56 2.91 ;
    END
  END i_target_set2[13]
  PIN i_target_set2[12]
    DIRECTION INPUT ;
    USE SIGNAL ;
    PORT
      LAYER met3 ;
        RECT 1907.09 610.83 1910 611.13 ;
    END
  END i_target_set2[12]
  PIN i_target_set2[11]
    DIRECTION INPUT ;
    USE SIGNAL ;
    PORT
      LAYER met2 ;
        RECT 581.06 2007.23 581.36 2010.14 ;
    END
  END i_target_set2[11]
  PIN i_target_set2[10]
    DIRECTION INPUT ;
    USE SIGNAL ;
    PORT
      LAYER met3 ;
        RECT 0 610.83 2.91 611.13 ;
    END
  END i_target_set2[10]
  PIN i_target_set2[9]
    DIRECTION INPUT ;
    USE SIGNAL ;
    PORT
      LAYER met2 ;
        RECT 612.8 0 613.1 2.91 ;
    END
  END i_target_set2[9]
  PIN i_target_set2[8]
    DIRECTION INPUT ;
    USE SIGNAL ;
    PORT
      LAYER met3 ;
        RECT 1907.09 660.47 1910 660.77 ;
    END
  END i_target_set2[8]
  PIN i_target_set2[7]
    DIRECTION INPUT ;
    USE SIGNAL ;
    PORT
      LAYER met2 ;
        RECT 627.52 2007.23 627.82 2010.14 ;
    END
  END i_target_set2[7]
  PIN i_target_set2[6]
    DIRECTION INPUT ;
    USE SIGNAL ;
    PORT
      LAYER met3 ;
        RECT 0 660.47 2.91 660.77 ;
    END
  END i_target_set2[6]
  PIN i_target_set2[5]
    DIRECTION INPUT ;
    USE SIGNAL ;
    PORT
      LAYER met2 ;
        RECT 658.34 0 658.64 2.91 ;
    END
  END i_target_set2[5]
  PIN i_target_set2[4]
    DIRECTION INPUT ;
    USE SIGNAL ;
    PORT
      LAYER met3 ;
        RECT 1907.09 709.43 1910 709.73 ;
    END
  END i_target_set2[4]
  PIN i_target_set2[3]
    DIRECTION INPUT ;
    USE SIGNAL ;
    PORT
      LAYER met2 ;
        RECT 674.44 2007.23 674.74 2010.14 ;
    END
  END i_target_set2[3]
  PIN i_target_set2[2]
    DIRECTION INPUT ;
    USE SIGNAL ;
    PORT
      LAYER met3 ;
        RECT 0 709.43 2.91 709.73 ;
    END
  END i_target_set2[2]
  PIN i_target_set2[1]
    DIRECTION INPUT ;
    USE SIGNAL ;
    PORT
      LAYER met2 ;
        RECT 703.88 0 704.18 2.91 ;
    END
  END i_target_set2[1]
  PIN i_target_set2[0]
    DIRECTION INPUT ;
    USE SIGNAL ;
    PORT
      LAYER met3 ;
        RECT 1907.09 758.39 1910 758.69 ;
    END
  END i_target_set2[0]
  PIN i_target_reset1[15]
    DIRECTION INPUT ;
    USE SIGNAL ;
    PORT
      LAYER met2 ;
        RECT 720.9 2007.23 721.2 2010.14 ;
    END
  END i_target_reset1[15]
  PIN i_target_reset1[14]
    DIRECTION INPUT ;
    USE SIGNAL ;
    PORT
      LAYER met3 ;
        RECT 0 758.39 2.91 758.69 ;
    END
  END i_target_reset1[14]
  PIN i_target_reset1[13]
    DIRECTION INPUT ;
    USE SIGNAL ;
    PORT
      LAYER met2 ;
        RECT 749.42 0 749.72 2.91 ;
    END
  END i_target_reset1[13]
  PIN i_target_reset1[12]
    DIRECTION INPUT ;
    USE SIGNAL ;
    PORT
      LAYER met3 ;
        RECT 1907.09 808.03 1910 808.33 ;
    END
  END i_target_reset1[12]
  PIN i_target_reset1[11]
    DIRECTION INPUT ;
    USE SIGNAL ;
    PORT
      LAYER met2 ;
        RECT 767.82 2007.23 768.12 2010.14 ;
    END
  END i_target_reset1[11]
  PIN i_target_reset1[10]
    DIRECTION INPUT ;
    USE SIGNAL ;
    PORT
      LAYER met3 ;
        RECT 0 808.03 2.91 808.33 ;
    END
  END i_target_reset1[10]
  PIN i_target_reset1[9]
    DIRECTION INPUT ;
    USE SIGNAL ;
    PORT
      LAYER met2 ;
        RECT 795.42 0 795.72 2.91 ;
    END
  END i_target_reset1[9]
  PIN i_target_reset1[8]
    DIRECTION INPUT ;
    USE SIGNAL ;
    PORT
      LAYER met3 ;
        RECT 1907.09 856.99 1910 857.29 ;
    END
  END i_target_reset1[8]
  PIN i_target_reset1[7]
    DIRECTION INPUT ;
    USE SIGNAL ;
    PORT
      LAYER met2 ;
        RECT 814.74 2007.23 815.04 2010.14 ;
    END
  END i_target_reset1[7]
  PIN i_target_reset1[6]
    DIRECTION INPUT ;
    USE SIGNAL ;
    PORT
      LAYER met3 ;
        RECT 0 856.99 2.91 857.29 ;
    END
  END i_target_reset1[6]
  PIN i_target_reset1[5]
    DIRECTION INPUT ;
    USE SIGNAL ;
    PORT
      LAYER met2 ;
        RECT 840.96 0 841.26 2.91 ;
    END
  END i_target_reset1[5]
  PIN i_target_reset1[4]
    DIRECTION INPUT ;
    USE SIGNAL ;
    PORT
      LAYER met3 ;
        RECT 1907.09 906.63 1910 906.93 ;
    END
  END i_target_reset1[4]
  PIN i_target_reset1[3]
    DIRECTION INPUT ;
    USE SIGNAL ;
    PORT
      LAYER met2 ;
        RECT 861.2 2007.23 861.5 2010.14 ;
    END
  END i_target_reset1[3]
  PIN i_target_reset1[2]
    DIRECTION INPUT ;
    USE SIGNAL ;
    PORT
      LAYER met3 ;
        RECT 0 906.63 2.91 906.93 ;
    END
  END i_target_reset1[2]
  PIN i_target_reset1[1]
    DIRECTION INPUT ;
    USE SIGNAL ;
    PORT
      LAYER met2 ;
        RECT 886.5 0 886.8 2.91 ;
    END
  END i_target_reset1[1]
  PIN i_target_reset1[0]
    DIRECTION INPUT ;
    USE SIGNAL ;
    PORT
      LAYER met3 ;
        RECT 1907.09 955.59 1910 955.89 ;
    END
  END i_target_reset1[0]
  PIN i_target_reset2[15]
    DIRECTION INPUT ;
    USE SIGNAL ;
    PORT
      LAYER met2 ;
        RECT 908.12 2007.23 908.42 2010.14 ;
    END
  END i_target_reset2[15]
  PIN i_target_reset2[14]
    DIRECTION INPUT ;
    USE SIGNAL ;
    PORT
      LAYER met3 ;
        RECT 0 955.59 2.91 955.89 ;
    END
  END i_target_reset2[14]
  PIN i_target_reset2[13]
    DIRECTION INPUT ;
    USE SIGNAL ;
    PORT
      LAYER met2 ;
        RECT 932.04 0 932.34 2.91 ;
    END
  END i_target_reset2[13]
  PIN i_target_reset2[12]
    DIRECTION INPUT ;
    USE SIGNAL ;
    PORT
      LAYER met3 ;
        RECT 1907.09 1005.23 1910 1005.53 ;
    END
  END i_target_reset2[12]
  PIN i_target_reset2[11]
    DIRECTION INPUT ;
    USE SIGNAL ;
    PORT
      LAYER met2 ;
        RECT 955.04 2007.23 955.34 2010.14 ;
    END
  END i_target_reset2[11]
  PIN i_target_reset2[10]
    DIRECTION INPUT ;
    USE SIGNAL ;
    PORT
      LAYER met3 ;
        RECT 0 1005.23 2.91 1005.53 ;
    END
  END i_target_reset2[10]
  PIN i_target_reset2[9]
    DIRECTION INPUT ;
    USE SIGNAL ;
    PORT
      LAYER met2 ;
        RECT 977.58 0 977.88 2.91 ;
    END
  END i_target_reset2[9]
  PIN i_target_reset2[8]
    DIRECTION INPUT ;
    USE SIGNAL ;
    PORT
      LAYER met3 ;
        RECT 1907.09 1054.19 1910 1054.49 ;
    END
  END i_target_reset2[8]
  PIN i_target_reset2[7]
    DIRECTION INPUT ;
    USE SIGNAL ;
    PORT
      LAYER met2 ;
        RECT 1001.5 2007.23 1001.8 2010.14 ;
    END
  END i_target_reset2[7]
  PIN i_target_reset2[6]
    DIRECTION INPUT ;
    USE SIGNAL ;
    PORT
      LAYER met3 ;
        RECT 0 1054.19 2.91 1054.49 ;
    END
  END i_target_reset2[6]
  PIN i_target_reset2[5]
    DIRECTION INPUT ;
    USE SIGNAL ;
    PORT
      LAYER met2 ;
        RECT 1023.12 0 1023.42 2.91 ;
    END
  END i_target_reset2[5]
  PIN i_target_reset2[4]
    DIRECTION INPUT ;
    USE SIGNAL ;
    PORT
      LAYER met3 ;
        RECT 1907.09 1103.15 1910 1103.45 ;
    END
  END i_target_reset2[4]
  PIN i_target_reset2[3]
    DIRECTION INPUT ;
    USE SIGNAL ;
    PORT
      LAYER met2 ;
        RECT 1048.42 2007.23 1048.72 2010.14 ;
    END
  END i_target_reset2[3]
  PIN i_target_reset2[2]
    DIRECTION INPUT ;
    USE SIGNAL ;
    PORT
      LAYER met3 ;
        RECT 0 1103.15 2.91 1103.45 ;
    END
  END i_target_reset2[2]
  PIN i_target_reset2[1]
    DIRECTION INPUT ;
    USE SIGNAL ;
    PORT
      LAYER met2 ;
        RECT 1068.66 0 1068.96 2.91 ;
    END
  END i_target_reset2[1]
  PIN i_target_reset2[0]
    DIRECTION INPUT ;
    USE SIGNAL ;
    PORT
      LAYER met3 ;
        RECT 1907.09 1152.79 1910 1153.09 ;
    END
  END i_target_reset2[0]
  PIN i_no_of_clk_cycles[9]
    DIRECTION INPUT ;
    USE SIGNAL ;
    PORT
      LAYER met2 ;
        RECT 1094.88 2007.23 1095.18 2010.14 ;
    END
  END i_no_of_clk_cycles[9]
  PIN i_no_of_clk_cycles[8]
    DIRECTION INPUT ;
    USE SIGNAL ;
    PORT
      LAYER met3 ;
        RECT 0 1152.79 2.91 1153.09 ;
    END
  END i_no_of_clk_cycles[8]
  PIN i_no_of_clk_cycles[7]
    DIRECTION INPUT ;
    USE SIGNAL ;
    PORT
      LAYER met2 ;
        RECT 1114.66 0 1114.96 2.91 ;
    END
  END i_no_of_clk_cycles[7]
  PIN i_no_of_clk_cycles[6]
    DIRECTION INPUT ;
    USE SIGNAL ;
    PORT
      LAYER met3 ;
        RECT 1907.09 1201.75 1910 1202.05 ;
    END
  END i_no_of_clk_cycles[6]
  PIN i_no_of_clk_cycles[5]
    DIRECTION INPUT ;
    USE SIGNAL ;
    PORT
      LAYER met2 ;
        RECT 1141.8 2007.23 1142.1 2010.14 ;
    END
  END i_no_of_clk_cycles[5]
  PIN i_no_of_clk_cycles[4]
    DIRECTION INPUT ;
    USE SIGNAL ;
    PORT
      LAYER met3 ;
        RECT 0 1201.75 2.91 1202.05 ;
    END
  END i_no_of_clk_cycles[4]
  PIN i_no_of_clk_cycles[3]
    DIRECTION INPUT ;
    USE SIGNAL ;
    PORT
      LAYER met2 ;
        RECT 1160.2 0 1160.5 2.91 ;
    END
  END i_no_of_clk_cycles[3]
  PIN i_no_of_clk_cycles[2]
    DIRECTION INPUT ;
    USE SIGNAL ;
    PORT
      LAYER met3 ;
        RECT 1907.09 1251.39 1910 1251.69 ;
    END
  END i_no_of_clk_cycles[2]
  PIN i_no_of_clk_cycles[1]
    DIRECTION INPUT ;
    USE SIGNAL ;
    PORT
      LAYER met2 ;
        RECT 1188.72 2007.23 1189.02 2010.14 ;
    END
  END i_no_of_clk_cycles[1]
  PIN i_no_of_clk_cycles[0]
    DIRECTION INPUT ;
    USE SIGNAL ;
    PORT
      LAYER met3 ;
        RECT 0 1251.39 2.91 1251.69 ;
    END
  END i_no_of_clk_cycles[0]
  PIN i_counter_value[9]
    DIRECTION INPUT ;
    USE SIGNAL ;
    PORT
      LAYER met2 ;
        RECT 1205.74 0 1206.04 2.91 ;
    END
  END i_counter_value[9]
  PIN i_counter_value[8]
    DIRECTION INPUT ;
    USE SIGNAL ;
    PORT
      LAYER met3 ;
        RECT 1907.09 1300.35 1910 1300.65 ;
    END
  END i_counter_value[8]
  PIN i_counter_value[7]
    DIRECTION INPUT ;
    USE SIGNAL ;
    PORT
      LAYER met2 ;
        RECT 1235.18 2007.23 1235.48 2010.14 ;
    END
  END i_counter_value[7]
  PIN i_counter_value[6]
    DIRECTION INPUT ;
    USE SIGNAL ;
    PORT
      LAYER met3 ;
        RECT 0 1300.35 2.91 1300.65 ;
    END
  END i_counter_value[6]
  PIN i_counter_value[5]
    DIRECTION INPUT ;
    USE SIGNAL ;
    PORT
      LAYER met2 ;
        RECT 1251.28 0 1251.58 2.91 ;
    END
  END i_counter_value[5]
  PIN i_counter_value[4]
    DIRECTION INPUT ;
    USE SIGNAL ;
    PORT
      LAYER met3 ;
        RECT 1907.09 1349.99 1910 1350.29 ;
    END
  END i_counter_value[4]
  PIN i_counter_value[3]
    DIRECTION INPUT ;
    USE SIGNAL ;
    PORT
      LAYER met2 ;
        RECT 1282.1 2007.23 1282.4 2010.14 ;
    END
  END i_counter_value[3]
  PIN i_counter_value[2]
    DIRECTION INPUT ;
    USE SIGNAL ;
    PORT
      LAYER met3 ;
        RECT 0 1349.99 2.91 1350.29 ;
    END
  END i_counter_value[2]
  PIN i_counter_value[1]
    DIRECTION INPUT ;
    USE SIGNAL ;
    PORT
      LAYER met2 ;
        RECT 1296.82 0 1297.12 2.91 ;
    END
  END i_counter_value[1]
  PIN i_counter_value[0]
    DIRECTION INPUT ;
    USE SIGNAL ;
    PORT
      LAYER met3 ;
        RECT 1907.09 1398.95 1910 1399.25 ;
    END
  END i_counter_value[0]
  PIN i_tdc_time_out[6]
    DIRECTION INPUT ;
    USE SIGNAL ;
    PORT
      LAYER met2 ;
        RECT 1329.02 2007.23 1329.32 2010.14 ;
    END
  END i_tdc_time_out[6]
  PIN i_tdc_time_out[5]
    DIRECTION INPUT ;
    USE SIGNAL ;
    PORT
      LAYER met3 ;
        RECT 0 1398.95 2.91 1399.25 ;
    END
  END i_tdc_time_out[5]
  PIN i_tdc_time_out[4]
    DIRECTION INPUT ;
    USE SIGNAL ;
    PORT
      LAYER met2 ;
        RECT 1342.36 0 1342.66 2.91 ;
    END
  END i_tdc_time_out[4]
  PIN i_tdc_time_out[3]
    DIRECTION INPUT ;
    USE SIGNAL ;
    PORT
      LAYER met3 ;
        RECT 1907.09 1447.91 1910 1448.21 ;
    END
  END i_tdc_time_out[3]
  PIN i_tdc_time_out[2]
    DIRECTION INPUT ;
    USE SIGNAL ;
    PORT
      LAYER met2 ;
        RECT 1375.48 2007.23 1375.78 2010.14 ;
    END
  END i_tdc_time_out[2]
  PIN i_tdc_time_out[1]
    DIRECTION INPUT ;
    USE SIGNAL ;
    PORT
      LAYER met3 ;
        RECT 0 1447.91 2.91 1448.21 ;
    END
  END i_tdc_time_out[1]
  PIN i_tdc_time_out[0]
    DIRECTION INPUT ;
    USE SIGNAL ;
    PORT
      LAYER met2 ;
        RECT 1388.36 0 1388.66 2.91 ;
    END
  END i_tdc_time_out[0]
  PIN i_tdc_dead_time[1]
    DIRECTION INPUT ;
    USE SIGNAL ;
    PORT
      LAYER met3 ;
        RECT 1907.09 1497.55 1910 1497.85 ;
    END
  END i_tdc_dead_time[1]
  PIN i_tdc_dead_time[0]
    DIRECTION INPUT ;
    USE SIGNAL ;
    PORT
      LAYER met2 ;
        RECT 1422.4 2007.23 1422.7 2010.14 ;
    END
  END i_tdc_dead_time[0]
  PIN o_busy
    DIRECTION OUTPUT ;
    USE SIGNAL ;
    PORT
      LAYER met3 ;
        RECT 0 1497.55 2.91 1497.85 ;
    END
  END o_busy
  PIN o_command_accepted
    DIRECTION OUTPUT ;
    USE SIGNAL ;
    PORT
      LAYER met2 ;
        RECT 1433.9 0 1434.2 2.91 ;
    END
  END o_command_accepted
  PIN o_compute_pending
    DIRECTION OUTPUT ;
    USE SIGNAL ;
    PORT
      LAYER met3 ;
        RECT 1907.09 1546.51 1910 1546.81 ;
    END
  END o_compute_pending
  PIN o_error[2]
    DIRECTION OUTPUT ;
    USE SIGNAL ;
    PORT
      LAYER met2 ;
        RECT 1469.32 2007.23 1469.62 2010.14 ;
    END
  END o_error[2]
  PIN o_error[1]
    DIRECTION OUTPUT ;
    USE SIGNAL ;
    PORT
      LAYER met3 ;
        RECT 0 1546.51 2.91 1546.81 ;
    END
  END o_error[1]
  PIN o_error[0]
    DIRECTION OUTPUT ;
    USE SIGNAL ;
    PORT
      LAYER met2 ;
        RECT 1479.44 0 1479.74 2.91 ;
    END
  END o_error[0]
  PIN o_error_valid
    DIRECTION OUTPUT ;
    USE SIGNAL ;
    PORT
      LAYER met3 ;
        RECT 1907.09 1596.15 1910 1596.45 ;
    END
  END o_error_valid
  PIN o_operation_done
    DIRECTION OUTPUT ;
    USE SIGNAL ;
    PORT
      LAYER met2 ;
        RECT 1515.78 2007.23 1516.08 2010.14 ;
    END
  END o_operation_done
  PIN o_program_readback_active
    DIRECTION OUTPUT ;
    USE SIGNAL ;
    PORT
      LAYER met3 ;
        RECT 0 1596.15 2.91 1596.45 ;
    END
  END o_program_readback_active
  PIN o_result_valid
    DIRECTION OUTPUT ;
    USE SIGNAL ;
    PORT
      LAYER met2 ;
        RECT 1524.98 0 1525.28 2.91 ;
    END
  END o_result_valid
  PIN i_result_ready
    DIRECTION INPUT ;
    USE SIGNAL ;
    PORT
      LAYER met3 ;
        RECT 1907.09 1645.11 1910 1645.41 ;
    END
  END i_result_ready
  PIN o_result_data[20]
    DIRECTION OUTPUT ;
    USE SIGNAL ;
    PORT
      LAYER met2 ;
        RECT 1562.7 2007.23 1563 2010.14 ;
    END
  END o_result_data[20]
  PIN o_result_data[19]
    DIRECTION OUTPUT ;
    USE SIGNAL ;
    PORT
      LAYER met3 ;
        RECT 0 1645.11 2.91 1645.41 ;
    END
  END o_result_data[19]
  PIN o_result_data[18]
    DIRECTION OUTPUT ;
    USE SIGNAL ;
    PORT
      LAYER met2 ;
        RECT 1570.52 0 1570.82 2.91 ;
    END
  END o_result_data[18]
  PIN o_result_data[17]
    DIRECTION OUTPUT ;
    USE SIGNAL ;
    PORT
      LAYER met3 ;
        RECT 1907.09 1694.75 1910 1695.05 ;
    END
  END o_result_data[17]
  PIN o_result_data[16]
    DIRECTION OUTPUT ;
    USE SIGNAL ;
    PORT
      LAYER met2 ;
        RECT 1609.16 2007.23 1609.46 2010.14 ;
    END
  END o_result_data[16]
  PIN o_result_data[15]
    DIRECTION OUTPUT ;
    USE SIGNAL ;
    PORT
      LAYER met3 ;
        RECT 0 1694.75 2.91 1695.05 ;
    END
  END o_result_data[15]
  PIN o_result_data[14]
    DIRECTION OUTPUT ;
    USE SIGNAL ;
    PORT
      LAYER met2 ;
        RECT 1616.06 0 1616.36 2.91 ;
    END
  END o_result_data[14]
  PIN o_result_data[13]
    DIRECTION OUTPUT ;
    USE SIGNAL ;
    PORT
      LAYER met3 ;
        RECT 1907.09 1743.71 1910 1744.01 ;
    END
  END o_result_data[13]
  PIN o_result_data[12]
    DIRECTION OUTPUT ;
    USE SIGNAL ;
    PORT
      LAYER met2 ;
        RECT 1656.08 2007.23 1656.38 2010.14 ;
    END
  END o_result_data[12]
  PIN o_result_data[11]
    DIRECTION OUTPUT ;
    USE SIGNAL ;
    PORT
      LAYER met3 ;
        RECT 0 1743.71 2.91 1744.01 ;
    END
  END o_result_data[11]
  PIN o_result_data[10]
    DIRECTION OUTPUT ;
    USE SIGNAL ;
    PORT
      LAYER met2 ;
        RECT 1661.6 0 1661.9 2.91 ;
    END
  END o_result_data[10]
  PIN o_result_data[9]
    DIRECTION OUTPUT ;
    USE SIGNAL ;
    PORT
      LAYER met3 ;
        RECT 1907.09 1792.67 1910 1792.97 ;
    END
  END o_result_data[9]
  PIN o_result_data[8]
    DIRECTION OUTPUT ;
    USE SIGNAL ;
    PORT
      LAYER met2 ;
        RECT 1703 2007.23 1703.3 2010.14 ;
    END
  END o_result_data[8]
  PIN o_result_data[7]
    DIRECTION OUTPUT ;
    USE SIGNAL ;
    PORT
      LAYER met3 ;
        RECT 0 1792.67 2.91 1792.97 ;
    END
  END o_result_data[7]
  PIN o_result_data[6]
    DIRECTION OUTPUT ;
    USE SIGNAL ;
    PORT
      LAYER met2 ;
        RECT 1707.6 0 1707.9 2.91 ;
    END
  END o_result_data[6]
  PIN o_result_data[5]
    DIRECTION OUTPUT ;
    USE SIGNAL ;
    PORT
      LAYER met3 ;
        RECT 1907.09 1842.31 1910 1842.61 ;
    END
  END o_result_data[5]
  PIN o_result_data[4]
    DIRECTION OUTPUT ;
    USE SIGNAL ;
    PORT
      LAYER met2 ;
        RECT 1749.46 2007.23 1749.76 2010.14 ;
    END
  END o_result_data[4]
  PIN o_result_data[3]
    DIRECTION OUTPUT ;
    USE SIGNAL ;
    PORT
      LAYER met3 ;
        RECT 0 1842.31 2.91 1842.61 ;
    END
  END o_result_data[3]
  PIN o_result_data[2]
    DIRECTION OUTPUT ;
    USE SIGNAL ;
    PORT
      LAYER met2 ;
        RECT 1753.14 0 1753.44 2.91 ;
    END
  END o_result_data[2]
  PIN o_result_data[1]
    DIRECTION OUTPUT ;
    USE SIGNAL ;
    PORT
      LAYER met3 ;
        RECT 1907.09 1891.27 1910 1891.57 ;
    END
  END o_result_data[1]
  PIN o_result_data[0]
    DIRECTION OUTPUT ;
    USE SIGNAL ;
    PORT
      LAYER met2 ;
        RECT 1796.38 2007.23 1796.68 2010.14 ;
    END
  END o_result_data[0]
  PIN o_result_last
    DIRECTION OUTPUT ;
    USE SIGNAL ;
    PORT
      LAYER met3 ;
        RECT 0 1891.27 2.91 1891.57 ;
    END
  END o_result_last
  PIN wbs_stb_i
    DIRECTION INPUT ;
    USE SIGNAL ;
    PORT
      LAYER met2 ;
        RECT 604.52 0 604.82 2.91 ;
    END
  END wbs_stb_i
  PIN wbs_cyc_i
    DIRECTION INPUT ;
    USE SIGNAL ;
    PORT
      LAYER met2 ;
        RECT 600.84 0 601.14 2.91 ;
    END
  END wbs_cyc_i
  PIN wbs_we_i
    DIRECTION INPUT ;
    USE SIGNAL ;
    PORT
      LAYER met2 ;
        RECT 607.28 0 607.58 2.91 ;
    END
  END wbs_we_i
  PIN wbs_sel_i[3]
    DIRECTION INPUT ;
    USE SIGNAL ;
    PORT
      LAYER met2 ;
        RECT 394.3 0 394.6 2.91 ;
    END
  END wbs_sel_i[3]
  PIN wbs_sel_i[2]
    DIRECTION INPUT ;
    USE SIGNAL ;
    PORT
      LAYER met2 ;
        RECT 397.98 0 398.28 2.91 ;
    END
  END wbs_sel_i[2]
  PIN wbs_sel_i[1]
    DIRECTION INPUT ;
    USE SIGNAL ;
    PORT
      LAYER met2 ;
        RECT 401.66 0 401.96 2.91 ;
    END
  END wbs_sel_i[1]
  PIN wbs_sel_i[0]
    DIRECTION INPUT ;
    USE SIGNAL ;
    PORT
      LAYER met2 ;
        RECT 405.34 0 405.64 2.91 ;
    END
  END wbs_sel_i[0]
  PIN wbs_dat_i[31]
    DIRECTION INPUT ;
    USE SIGNAL ;
    PORT
      LAYER met2 ;
        RECT 1073.26 0 1073.56 2.91 ;
    END
  END wbs_dat_i[31]
  PIN wbs_dat_i[30]
    DIRECTION INPUT ;
    USE SIGNAL ;
    PORT
      LAYER met2 ;
        RECT 1066.36 0 1066.66 2.91 ;
    END
  END wbs_dat_i[30]
  PIN wbs_dat_i[29]
    DIRECTION INPUT ;
    USE SIGNAL ;
    PORT
      LAYER met2 ;
        RECT 1059 0 1059.3 2.91 ;
    END
  END wbs_dat_i[29]
  PIN wbs_dat_i[28]
    DIRECTION INPUT ;
    USE SIGNAL ;
    PORT
      LAYER met2 ;
        RECT 1052.1 0 1052.4 2.91 ;
    END
  END wbs_dat_i[28]
  PIN wbs_dat_i[27]
    DIRECTION INPUT ;
    USE SIGNAL ;
    PORT
      LAYER met2 ;
        RECT 1044.74 0 1045.04 2.91 ;
    END
  END wbs_dat_i[27]
  PIN wbs_dat_i[26]
    DIRECTION INPUT ;
    USE SIGNAL ;
    PORT
      LAYER met2 ;
        RECT 1037.38 0 1037.68 2.91 ;
    END
  END wbs_dat_i[26]
  PIN wbs_dat_i[25]
    DIRECTION INPUT ;
    USE SIGNAL ;
    PORT
      LAYER met2 ;
        RECT 1030.02 0 1030.32 2.91 ;
    END
  END wbs_dat_i[25]
  PIN wbs_dat_i[24]
    DIRECTION INPUT ;
    USE SIGNAL ;
    PORT
      LAYER met2 ;
        RECT 1024.04 0 1024.34 2.91 ;
    END
  END wbs_dat_i[24]
  PIN wbs_dat_i[23]
    DIRECTION INPUT ;
    USE SIGNAL ;
    PORT
      LAYER met2 ;
        RECT 1015.76 0 1016.06 2.91 ;
    END
  END wbs_dat_i[23]
  PIN wbs_dat_i[22]
    DIRECTION INPUT ;
    USE SIGNAL ;
    PORT
      LAYER met2 ;
        RECT 1008.86 0 1009.16 2.91 ;
    END
  END wbs_dat_i[22]
  PIN wbs_dat_i[21]
    DIRECTION INPUT ;
    USE SIGNAL ;
    PORT
      LAYER met2 ;
        RECT 1001.5 0 1001.8 2.91 ;
    END
  END wbs_dat_i[21]
  PIN wbs_dat_i[20]
    DIRECTION INPUT ;
    USE SIGNAL ;
    PORT
      LAYER met2 ;
        RECT 994.14 0 994.44 2.91 ;
    END
  END wbs_dat_i[20]
  PIN wbs_dat_i[19]
    DIRECTION INPUT ;
    USE SIGNAL ;
    PORT
      LAYER met2 ;
        RECT 986.78 0 987.08 2.91 ;
    END
  END wbs_dat_i[19]
  PIN wbs_dat_i[18]
    DIRECTION INPUT ;
    USE SIGNAL ;
    PORT
      LAYER met2 ;
        RECT 979.88 0 980.18 2.91 ;
    END
  END wbs_dat_i[18]
  PIN wbs_dat_i[17]
    DIRECTION INPUT ;
    USE SIGNAL ;
    PORT
      LAYER met2 ;
        RECT 972.52 0 972.82 2.91 ;
    END
  END wbs_dat_i[17]
  PIN wbs_dat_i[16]
    DIRECTION INPUT ;
    USE SIGNAL ;
    PORT
      LAYER met2 ;
        RECT 965.62 0 965.92 2.91 ;
    END
  END wbs_dat_i[16]
  PIN wbs_dat_i[15]
    DIRECTION INPUT ;
    USE SIGNAL ;
    PORT
      LAYER met2 ;
        RECT 958.26 0 958.56 2.91 ;
    END
  END wbs_dat_i[15]
  PIN wbs_dat_i[14]
    DIRECTION INPUT ;
    USE SIGNAL ;
    PORT
      LAYER met2 ;
        RECT 950.9 0 951.2 2.91 ;
    END
  END wbs_dat_i[14]
  PIN wbs_dat_i[13]
    DIRECTION INPUT ;
    USE SIGNAL ;
    PORT
      LAYER met2 ;
        RECT 943.54 0 943.84 2.91 ;
    END
  END wbs_dat_i[13]
  PIN wbs_dat_i[12]
    DIRECTION INPUT ;
    USE SIGNAL ;
    PORT
      LAYER met2 ;
        RECT 936.64 0 936.94 2.91 ;
    END
  END wbs_dat_i[12]
  PIN wbs_dat_i[11]
    DIRECTION INPUT ;
    USE SIGNAL ;
    PORT
      LAYER met2 ;
        RECT 929.28 0 929.58 2.91 ;
    END
  END wbs_dat_i[11]
  PIN wbs_dat_i[10]
    DIRECTION INPUT ;
    USE SIGNAL ;
    PORT
      LAYER met2 ;
        RECT 922.38 0 922.68 2.91 ;
    END
  END wbs_dat_i[10]
  PIN wbs_dat_i[9]
    DIRECTION INPUT ;
    USE SIGNAL ;
    PORT
      LAYER met2 ;
        RECT 915.02 0 915.32 2.91 ;
    END
  END wbs_dat_i[9]
  PIN wbs_dat_i[8]
    DIRECTION INPUT ;
    USE SIGNAL ;
    PORT
      LAYER met2 ;
        RECT 907.66 0 907.96 2.91 ;
    END
  END wbs_dat_i[8]
  PIN wbs_dat_i[7]
    DIRECTION INPUT ;
    USE SIGNAL ;
    PORT
      LAYER met2 ;
        RECT 900.76 0 901.06 2.91 ;
    END
  END wbs_dat_i[7]
  PIN wbs_dat_i[6]
    DIRECTION INPUT ;
    USE SIGNAL ;
    PORT
      LAYER met2 ;
        RECT 893.4 0 893.7 2.91 ;
    END
  END wbs_dat_i[6]
  PIN wbs_dat_i[5]
    DIRECTION INPUT ;
    USE SIGNAL ;
    PORT
      LAYER met2 ;
        RECT 887.42 0 887.72 2.91 ;
    END
  END wbs_dat_i[5]
  PIN wbs_dat_i[4]
    DIRECTION INPUT ;
    USE SIGNAL ;
    PORT
      LAYER met2 ;
        RECT 879.14 0 879.44 2.91 ;
    END
  END wbs_dat_i[4]
  PIN wbs_dat_i[3]
    DIRECTION INPUT ;
    USE SIGNAL ;
    PORT
      LAYER met2 ;
        RECT 871.78 0 872.08 2.91 ;
    END
  END wbs_dat_i[3]
  PIN wbs_dat_i[2]
    DIRECTION INPUT ;
    USE SIGNAL ;
    PORT
      LAYER met2 ;
        RECT 864.42 0 864.72 2.91 ;
    END
  END wbs_dat_i[2]
  PIN wbs_dat_i[1]
    DIRECTION INPUT ;
    USE SIGNAL ;
    PORT
      LAYER met2 ;
        RECT 857.52 0 857.82 2.91 ;
    END
  END wbs_dat_i[1]
  PIN wbs_dat_i[0]
    DIRECTION INPUT ;
    USE SIGNAL ;
    PORT
      LAYER met2 ;
        RECT 850.16 0 850.46 2.91 ;
    END
  END wbs_dat_i[0]
  PIN wbs_adr_i[31]
    DIRECTION INPUT ;
    USE SIGNAL ;
    PORT
      LAYER met2 ;
        RECT 357.96 0 358.26 2.91 ;
    END
  END wbs_adr_i[31]
  PIN wbs_adr_i[30]
    DIRECTION INPUT ;
    USE SIGNAL ;
    PORT
      LAYER met2 ;
        RECT 354.74 0 355.04 2.91 ;
    END
  END wbs_adr_i[30]
  PIN wbs_adr_i[29]
    DIRECTION INPUT ;
    USE SIGNAL ;
    PORT
      LAYER met2 ;
        RECT 350.6 0 350.9 2.91 ;
    END
  END wbs_adr_i[29]
  PIN wbs_adr_i[28]
    DIRECTION INPUT ;
    USE SIGNAL ;
    PORT
      LAYER met2 ;
        RECT 347.38 0 347.68 2.91 ;
    END
  END wbs_adr_i[28]
  PIN wbs_adr_i[27]
    DIRECTION INPUT ;
    USE SIGNAL ;
    PORT
      LAYER met2 ;
        RECT 343.7 0 344 2.91 ;
    END
  END wbs_adr_i[27]
  PIN wbs_adr_i[26]
    DIRECTION INPUT ;
    USE SIGNAL ;
    PORT
      LAYER met2 ;
        RECT 340.02 0 340.32 2.91 ;
    END
  END wbs_adr_i[26]
  PIN wbs_adr_i[25]
    DIRECTION INPUT ;
    USE SIGNAL ;
    PORT
      LAYER met2 ;
        RECT 336.34 0 336.64 2.91 ;
    END
  END wbs_adr_i[25]
  PIN wbs_adr_i[24]
    DIRECTION INPUT ;
    USE SIGNAL ;
    PORT
      LAYER met2 ;
        RECT 332.66 0 332.96 2.91 ;
    END
  END wbs_adr_i[24]
  PIN wbs_adr_i[23]
    DIRECTION INPUT ;
    USE SIGNAL ;
    PORT
      LAYER met2 ;
        RECT 329.44 0 329.74 2.91 ;
    END
  END wbs_adr_i[23]
  PIN wbs_adr_i[22]
    DIRECTION INPUT ;
    USE SIGNAL ;
    PORT
      LAYER met2 ;
        RECT 325.76 0 326.06 2.91 ;
    END
  END wbs_adr_i[22]
  PIN wbs_adr_i[21]
    DIRECTION INPUT ;
    USE SIGNAL ;
    PORT
      LAYER met2 ;
        RECT 322.08 0 322.38 2.91 ;
    END
  END wbs_adr_i[21]
  PIN wbs_adr_i[20]
    DIRECTION INPUT ;
    USE SIGNAL ;
    PORT
      LAYER met2 ;
        RECT 318.4 0 318.7 2.91 ;
    END
  END wbs_adr_i[20]
  PIN wbs_adr_i[19]
    DIRECTION INPUT ;
    USE SIGNAL ;
    PORT
      LAYER met2 ;
        RECT 314.72 0 315.02 2.91 ;
    END
  END wbs_adr_i[19]
  PIN wbs_adr_i[18]
    DIRECTION INPUT ;
    USE SIGNAL ;
    PORT
      LAYER met2 ;
        RECT 311.5 0 311.8 2.91 ;
    END
  END wbs_adr_i[18]
  PIN wbs_adr_i[17]
    DIRECTION INPUT ;
    USE SIGNAL ;
    PORT
      LAYER met2 ;
        RECT 307.82 0 308.12 2.91 ;
    END
  END wbs_adr_i[17]
  PIN wbs_adr_i[16]
    DIRECTION INPUT ;
    USE SIGNAL ;
    PORT
      LAYER met2 ;
        RECT 303.68 0 303.98 2.91 ;
    END
  END wbs_adr_i[16]
  PIN wbs_adr_i[15]
    DIRECTION INPUT ;
    USE SIGNAL ;
    PORT
      LAYER met2 ;
        RECT 300.46 0 300.76 2.91 ;
    END
  END wbs_adr_i[15]
  PIN wbs_adr_i[14]
    DIRECTION INPUT ;
    USE SIGNAL ;
    PORT
      LAYER met2 ;
        RECT 296.78 0 297.08 2.91 ;
    END
  END wbs_adr_i[14]
  PIN wbs_adr_i[13]
    DIRECTION INPUT ;
    USE SIGNAL ;
    PORT
      LAYER met2 ;
        RECT 294.48 0 294.78 2.91 ;
    END
  END wbs_adr_i[13]
  PIN wbs_adr_i[12]
    DIRECTION INPUT ;
    USE SIGNAL ;
    PORT
      LAYER met2 ;
        RECT 289.42 0 289.72 2.91 ;
    END
  END wbs_adr_i[12]
  PIN wbs_adr_i[11]
    DIRECTION INPUT ;
    USE SIGNAL ;
    PORT
      LAYER met2 ;
        RECT 286.2 0 286.5 2.91 ;
    END
  END wbs_adr_i[11]
  PIN wbs_adr_i[10]
    DIRECTION INPUT ;
    USE SIGNAL ;
    PORT
      LAYER met2 ;
        RECT 282.52 0 282.82 2.91 ;
    END
  END wbs_adr_i[10]
  PIN wbs_adr_i[9]
    DIRECTION INPUT ;
    USE SIGNAL ;
    PORT
      LAYER met2 ;
        RECT 278.84 0 279.14 2.91 ;
    END
  END wbs_adr_i[9]
  PIN wbs_adr_i[8]
    DIRECTION INPUT ;
    USE SIGNAL ;
    PORT
      LAYER met2 ;
        RECT 275.16 0 275.46 2.91 ;
    END
  END wbs_adr_i[8]
  PIN wbs_adr_i[7]
    DIRECTION INPUT ;
    USE SIGNAL ;
    PORT
      LAYER met2 ;
        RECT 271.48 0 271.78 2.91 ;
    END
  END wbs_adr_i[7]
  PIN wbs_adr_i[6]
    DIRECTION INPUT ;
    USE SIGNAL ;
    PORT
      LAYER met2 ;
        RECT 268.26 0 268.56 2.91 ;
    END
  END wbs_adr_i[6]
  PIN wbs_adr_i[5]
    DIRECTION INPUT ;
    USE SIGNAL ;
    PORT
      LAYER met2 ;
        RECT 264.58 0 264.88 2.91 ;
    END
  END wbs_adr_i[5]
  PIN wbs_adr_i[4]
    DIRECTION INPUT ;
    USE SIGNAL ;
    PORT
      LAYER met2 ;
        RECT 260.9 0 261.2 2.91 ;
    END
  END wbs_adr_i[4]
  PIN wbs_adr_i[3]
    DIRECTION INPUT ;
    USE SIGNAL ;
    PORT
      LAYER met2 ;
        RECT 257.22 0 257.52 2.91 ;
    END
  END wbs_adr_i[3]
  PIN wbs_adr_i[2]
    DIRECTION INPUT ;
    USE SIGNAL ;
    PORT
      LAYER met2 ;
        RECT 253.54 0 253.84 2.91 ;
    END
  END wbs_adr_i[2]
  PIN wbs_adr_i[1]
    DIRECTION INPUT ;
    USE SIGNAL ;
    PORT
      LAYER met2 ;
        RECT 250.32 0 250.62 2.91 ;
    END
  END wbs_adr_i[1]
  PIN wbs_adr_i[0]
    DIRECTION INPUT ;
    USE SIGNAL ;
    PORT
      LAYER met2 ;
        RECT 246.64 0 246.94 2.91 ;
    END
  END wbs_adr_i[0]
  PIN wbs_dat_o[31]
    DIRECTION OUTPUT ;
    USE SIGNAL ;
    PORT
      LAYER met2 ;
        RECT 1400.78 0 1401.08 2.91 ;
    END
  END wbs_dat_o[31]
  PIN wbs_dat_o[30]
    DIRECTION OUTPUT ;
    USE SIGNAL ;
    PORT
      LAYER met2 ;
        RECT 1393.42 0 1393.72 2.91 ;
    END
  END wbs_dat_o[30]
  PIN wbs_dat_o[29]
    DIRECTION OUTPUT ;
    USE SIGNAL ;
    PORT
      LAYER met2 ;
        RECT 1386.52 0 1386.82 2.91 ;
    END
  END wbs_dat_o[29]
  PIN wbs_dat_o[28]
    DIRECTION OUTPUT ;
    USE SIGNAL ;
    PORT
      LAYER met2 ;
        RECT 1379.16 0 1379.46 2.91 ;
    END
  END wbs_dat_o[28]
  PIN wbs_dat_o[27]
    DIRECTION OUTPUT ;
    USE SIGNAL ;
    PORT
      LAYER met2 ;
        RECT 1372.26 0 1372.56 2.91 ;
    END
  END wbs_dat_o[27]
  PIN wbs_dat_o[26]
    DIRECTION OUTPUT ;
    USE SIGNAL ;
    PORT
      LAYER met2 ;
        RECT 1364.9 0 1365.2 2.91 ;
    END
  END wbs_dat_o[26]
  PIN wbs_dat_o[25]
    DIRECTION OUTPUT ;
    USE SIGNAL ;
    PORT
      LAYER met2 ;
        RECT 1357.54 0 1357.84 2.91 ;
    END
  END wbs_dat_o[25]
  PIN wbs_dat_o[24]
    DIRECTION OUTPUT ;
    USE SIGNAL ;
    PORT
      LAYER met2 ;
        RECT 1350.18 0 1350.48 2.91 ;
    END
  END wbs_dat_o[24]
  PIN wbs_dat_o[23]
    DIRECTION OUTPUT ;
    USE SIGNAL ;
    PORT
      LAYER met2 ;
        RECT 1343.28 0 1343.58 2.91 ;
    END
  END wbs_dat_o[23]
  PIN wbs_dat_o[22]
    DIRECTION OUTPUT ;
    USE SIGNAL ;
    PORT
      LAYER met2 ;
        RECT 1335.92 0 1336.22 2.91 ;
    END
  END wbs_dat_o[22]
  PIN wbs_dat_o[21]
    DIRECTION OUTPUT ;
    USE SIGNAL ;
    PORT
      LAYER met2 ;
        RECT 1328.56 0 1328.86 2.91 ;
    END
  END wbs_dat_o[21]
  PIN wbs_dat_o[20]
    DIRECTION OUTPUT ;
    USE SIGNAL ;
    PORT
      LAYER met2 ;
        RECT 1321.66 0 1321.96 2.91 ;
    END
  END wbs_dat_o[20]
  PIN wbs_dat_o[19]
    DIRECTION OUTPUT ;
    USE SIGNAL ;
    PORT
      LAYER met2 ;
        RECT 1314.3 0 1314.6 2.91 ;
    END
  END wbs_dat_o[19]
  PIN wbs_dat_o[18]
    DIRECTION OUTPUT ;
    USE SIGNAL ;
    PORT
      LAYER met2 ;
        RECT 1307.4 0 1307.7 2.91 ;
    END
  END wbs_dat_o[18]
  PIN wbs_dat_o[17]
    DIRECTION OUTPUT ;
    USE SIGNAL ;
    PORT
      LAYER met2 ;
        RECT 1300.04 0 1300.34 2.91 ;
    END
  END wbs_dat_o[17]
  PIN wbs_dat_o[16]
    DIRECTION OUTPUT ;
    USE SIGNAL ;
    PORT
      LAYER met2 ;
        RECT 1293.14 0 1293.44 2.91 ;
    END
  END wbs_dat_o[16]
  PIN wbs_dat_o[15]
    DIRECTION OUTPUT ;
    USE SIGNAL ;
    PORT
      LAYER met2 ;
        RECT 1285.32 0 1285.62 2.91 ;
    END
  END wbs_dat_o[15]
  PIN wbs_dat_o[14]
    DIRECTION OUTPUT ;
    USE SIGNAL ;
    PORT
      LAYER met2 ;
        RECT 1278.42 0 1278.72 2.91 ;
    END
  END wbs_dat_o[14]
  PIN wbs_dat_o[13]
    DIRECTION OUTPUT ;
    USE SIGNAL ;
    PORT
      LAYER met2 ;
        RECT 1271.06 0 1271.36 2.91 ;
    END
  END wbs_dat_o[13]
  PIN wbs_dat_o[12]
    DIRECTION OUTPUT ;
    USE SIGNAL ;
    PORT
      LAYER met2 ;
        RECT 1264.16 0 1264.46 2.91 ;
    END
  END wbs_dat_o[12]
  PIN wbs_dat_o[11]
    DIRECTION OUTPUT ;
    USE SIGNAL ;
    PORT
      LAYER met2 ;
        RECT 1256.8 0 1257.1 2.91 ;
    END
  END wbs_dat_o[11]
  PIN wbs_dat_o[10]
    DIRECTION OUTPUT ;
    USE SIGNAL ;
    PORT
      LAYER met2 ;
        RECT 1249.9 0 1250.2 2.91 ;
    END
  END wbs_dat_o[10]
  PIN wbs_dat_o[9]
    DIRECTION OUTPUT ;
    USE SIGNAL ;
    PORT
      LAYER met2 ;
        RECT 1242.08 0 1242.38 2.91 ;
    END
  END wbs_dat_o[9]
  PIN wbs_dat_o[8]
    DIRECTION OUTPUT ;
    USE SIGNAL ;
    PORT
      LAYER met2 ;
        RECT 1235.18 0 1235.48 2.91 ;
    END
  END wbs_dat_o[8]
  PIN wbs_dat_o[7]
    DIRECTION OUTPUT ;
    USE SIGNAL ;
    PORT
      LAYER met2 ;
        RECT 1227.82 0 1228.12 2.91 ;
    END
  END wbs_dat_o[7]
  PIN wbs_dat_o[6]
    DIRECTION OUTPUT ;
    USE SIGNAL ;
    PORT
      LAYER met2 ;
        RECT 1220.92 0 1221.22 2.91 ;
    END
  END wbs_dat_o[6]
  PIN wbs_dat_o[5]
    DIRECTION OUTPUT ;
    USE SIGNAL ;
    PORT
      LAYER met2 ;
        RECT 1213.56 0 1213.86 2.91 ;
    END
  END wbs_dat_o[5]
  PIN wbs_dat_o[4]
    DIRECTION OUTPUT ;
    USE SIGNAL ;
    PORT
      LAYER met2 ;
        RECT 1206.66 0 1206.96 2.91 ;
    END
  END wbs_dat_o[4]
  PIN wbs_dat_o[3]
    DIRECTION OUTPUT ;
    USE SIGNAL ;
    PORT
      LAYER met2 ;
        RECT 1199.3 0 1199.6 2.91 ;
    END
  END wbs_dat_o[3]
  PIN wbs_dat_o[2]
    DIRECTION OUTPUT ;
    USE SIGNAL ;
    PORT
      LAYER met2 ;
        RECT 1191.94 0 1192.24 2.91 ;
    END
  END wbs_dat_o[2]
  PIN wbs_dat_o[1]
    DIRECTION OUTPUT ;
    USE SIGNAL ;
    PORT
      LAYER met2 ;
        RECT 1185.04 0 1185.34 2.91 ;
    END
  END wbs_dat_o[1]
  PIN wbs_dat_o[0]
    DIRECTION OUTPUT ;
    USE SIGNAL ;
    PORT
      LAYER met2 ;
        RECT 1177.68 0 1177.98 2.91 ;
    END
  END wbs_dat_o[0]
  PIN wbs_ack_o
    DIRECTION OUTPUT ;
    USE SIGNAL ;
    PORT
      LAYER met2 ;
        RECT 614.64 0 614.94 2.91 ;
    END
  END wbs_ack_o
  PIN stop_bit_i[31]
    DIRECTION INPUT ;
    USE SIGNAL ;
    PORT
      LAYER met2 ;
        RECT 227.78 2007.23 228.08 2010.14 ;
    END
  END stop_bit_i[31]
  PIN stop_bit_i[30]
    DIRECTION INPUT ;
    USE SIGNAL ;
    PORT
      LAYER met3 ;
        RECT 0 238.87 2.91 239.17 ;
    END
  END stop_bit_i[30]
  PIN stop_bit_i[29]
    DIRECTION INPUT ;
    USE SIGNAL ;
    PORT
      LAYER met2 ;
        RECT 393.38 0 393.68 2.91 ;
    END
  END stop_bit_i[29]
  PIN stop_bit_i[28]
    DIRECTION INPUT ;
    USE SIGNAL ;
    PORT
      LAYER met3 ;
        RECT 1907.09 414.31 1910 414.61 ;
    END
  END stop_bit_i[28]
  PIN stop_bit_i[27]
    DIRECTION INPUT ;
    USE SIGNAL ;
    PORT
      LAYER met2 ;
        RECT 435.24 2007.23 435.54 2010.14 ;
    END
  END stop_bit_i[27]
  PIN stop_bit_i[26]
    DIRECTION INPUT ;
    USE SIGNAL ;
    PORT
      LAYER met3 ;
        RECT 0 457.83 2.91 458.13 ;
    END
  END stop_bit_i[26]
  PIN stop_bit_i[25]
    DIRECTION INPUT ;
    USE SIGNAL ;
    PORT
      LAYER met2 ;
        RECT 581.06 0 581.36 2.91 ;
    END
  END stop_bit_i[25]
  PIN stop_bit_i[24]
    DIRECTION INPUT ;
    USE SIGNAL ;
    PORT
      LAYER met3 ;
        RECT 1907.09 611.51 1910 611.81 ;
    END
  END stop_bit_i[24]
  PIN stop_bit_i[23]
    DIRECTION INPUT ;
    USE SIGNAL ;
    PORT
      LAYER met2 ;
        RECT 643.16 2007.23 643.46 2010.14 ;
    END
  END stop_bit_i[23]
  PIN stop_bit_i[22]
    DIRECTION INPUT ;
    USE SIGNAL ;
    PORT
      LAYER met3 ;
        RECT 0 676.79 2.91 677.09 ;
    END
  END stop_bit_i[22]
  PIN stop_bit_i[21]
    DIRECTION INPUT ;
    USE SIGNAL ;
    PORT
      LAYER met2 ;
        RECT 767.82 0 768.12 2.91 ;
    END
  END stop_bit_i[21]
  PIN stop_bit_i[20]
    DIRECTION INPUT ;
    USE SIGNAL ;
    PORT
      LAYER met3 ;
        RECT 1907.09 808.71 1910 809.01 ;
    END
  END stop_bit_i[20]
  PIN stop_bit_i[19]
    DIRECTION INPUT ;
    USE SIGNAL ;
    PORT
      LAYER met2 ;
        RECT 851.08 2007.23 851.38 2010.14 ;
    END
  END stop_bit_i[19]
  PIN stop_bit_i[18]
    DIRECTION INPUT ;
    USE SIGNAL ;
    PORT
      LAYER met3 ;
        RECT 0 895.75 2.91 896.05 ;
    END
  END stop_bit_i[18]
  PIN stop_bit_i[17]
    DIRECTION INPUT ;
    USE SIGNAL ;
    PORT
      LAYER met2 ;
        RECT 955.04 0 955.34 2.91 ;
    END
  END stop_bit_i[17]
  PIN stop_bit_i[16]
    DIRECTION INPUT ;
    USE SIGNAL ;
    PORT
      LAYER met3 ;
        RECT 1907.09 1005.91 1910 1006.21 ;
    END
  END stop_bit_i[16]
  PIN stop_bit_i[15]
    DIRECTION INPUT ;
    USE SIGNAL ;
    PORT
      LAYER met2 ;
        RECT 1058.54 2007.23 1058.84 2010.14 ;
    END
  END stop_bit_i[15]
  PIN stop_bit_i[14]
    DIRECTION INPUT ;
    USE SIGNAL ;
    PORT
      LAYER met3 ;
        RECT 0 1114.03 2.91 1114.33 ;
    END
  END stop_bit_i[14]
  PIN stop_bit_i[13]
    DIRECTION INPUT ;
    USE SIGNAL ;
    PORT
      LAYER met2 ;
        RECT 1141.8 0 1142.1 2.91 ;
    END
  END stop_bit_i[13]
  PIN stop_bit_i[12]
    DIRECTION INPUT ;
    USE SIGNAL ;
    PORT
      LAYER met3 ;
        RECT 1907.09 1202.43 1910 1202.73 ;
    END
  END stop_bit_i[12]
  PIN stop_bit_i[11]
    DIRECTION INPUT ;
    USE SIGNAL ;
    PORT
      LAYER met2 ;
        RECT 1266.46 2007.23 1266.76 2010.14 ;
    END
  END stop_bit_i[11]
  PIN stop_bit_i[10]
    DIRECTION INPUT ;
    USE SIGNAL ;
    PORT
      LAYER met3 ;
        RECT 0 1332.99 2.91 1333.29 ;
    END
  END stop_bit_i[10]
  PIN stop_bit_i[9]
    DIRECTION INPUT ;
    USE SIGNAL ;
    PORT
      LAYER met2 ;
        RECT 1329.48 0 1329.78 2.91 ;
    END
  END stop_bit_i[9]
  PIN stop_bit_i[8]
    DIRECTION INPUT ;
    USE SIGNAL ;
    PORT
      LAYER met3 ;
        RECT 1907.09 1399.63 1910 1399.93 ;
    END
  END stop_bit_i[8]
  PIN stop_bit_i[7]
    DIRECTION INPUT ;
    USE SIGNAL ;
    PORT
      LAYER met2 ;
        RECT 1474.38 2007.23 1474.68 2010.14 ;
    END
  END stop_bit_i[7]
  PIN stop_bit_i[6]
    DIRECTION INPUT ;
    USE SIGNAL ;
    PORT
      LAYER met3 ;
        RECT 0 1551.95 2.91 1552.25 ;
    END
  END stop_bit_i[6]
  PIN stop_bit_i[5]
    DIRECTION INPUT ;
    USE SIGNAL ;
    PORT
      LAYER met2 ;
        RECT 1515.78 0 1516.08 2.91 ;
    END
  END stop_bit_i[5]
  PIN stop_bit_i[4]
    DIRECTION INPUT ;
    USE SIGNAL ;
    PORT
      LAYER met3 ;
        RECT 1907.09 1596.83 1910 1597.13 ;
    END
  END stop_bit_i[4]
  PIN stop_bit_i[3]
    DIRECTION INPUT ;
    USE SIGNAL ;
    PORT
      LAYER met2 ;
        RECT 1682.3 2007.23 1682.6 2010.14 ;
    END
  END stop_bit_i[3]
  PIN stop_bit_i[2]
    DIRECTION INPUT ;
    USE SIGNAL ;
    PORT
      LAYER met3 ;
        RECT 0 1770.91 2.91 1771.21 ;
    END
  END stop_bit_i[2]
  PIN stop_bit_i[1]
    DIRECTION INPUT ;
    USE SIGNAL ;
    PORT
      LAYER met2 ;
        RECT 1703 0 1703.3 2.91 ;
    END
  END stop_bit_i[1]
  PIN stop_bit_i[0]
    DIRECTION INPUT ;
    USE SIGNAL ;
    PORT
      LAYER met3 ;
        RECT 1907.09 1793.35 1910 1793.65 ;
    END
  END stop_bit_i[0]
  PIN ScanInCC
    DIRECTION INPUT ;
    USE SIGNAL ;
    PORT
      LAYER met2 ;
        RECT 1798.68 0 1798.98 2.91 ;
    END
  END ScanInCC
  PIN ScanInDL
    DIRECTION INPUT ;
    USE SIGNAL ;
    PORT
      LAYER met3 ;
        RECT 1907.09 1940.91 1910 1941.21 ;
    END
  END ScanInDL
  PIN ScanInDR
    DIRECTION INPUT ;
    USE SIGNAL ;
    PORT
      LAYER met2 ;
        RECT 1843.3 2007.23 1843.6 2010.14 ;
    END
  END ScanInDR
  PIN ScanOutCC
    DIRECTION OUTPUT ;
    USE SIGNAL ;
    PORT
      LAYER met3 ;
        RECT 0 1940.91 2.91 1941.21 ;
    END
  END ScanOutCC
  PIN TM
    DIRECTION INPUT ;
    USE SIGNAL ;
    PORT
      LAYER met2 ;
        RECT 1844.22 0 1844.52 2.91 ;
    END
  END TM
  PIN Iref
    DIRECTION INOUT ;
    USE SIGNAL ;
    PORT
      LAYER met3 ;
        RECT 0 1427.69 20 1428.99 ;
    END
  END Iref
  PIN Vcc_read
    DIRECTION INOUT ;
    USE SIGNAL ;
    PORT
      LAYER met3 ;
        RECT 1890 1468.49 1910 1469.79 ;
    END
  END Vcc_read
  PIN Vcomp
    DIRECTION INOUT ;
    USE SIGNAL ;
    PORT
      LAYER met3 ;
        RECT 0 1509.29 20 1510.59 ;
    END
  END Vcomp
  PIN Bias_comp2
    DIRECTION INOUT ;
    USE SIGNAL ;
    PORT
      LAYER met3 ;
        RECT 1890 1550.09 1910 1551.39 ;
    END
  END Bias_comp2
  PIN Vcc_wl_read
    DIRECTION INOUT ;
    USE SIGNAL ;
    PORT
      LAYER met3 ;
        RECT 0 1590.89 20 1592.19 ;
    END
  END Vcc_wl_read
  PIN Vcc_wl_set
    DIRECTION INOUT ;
    USE SIGNAL ;
    PORT
      LAYER met3 ;
        RECT 1890 1631.69 1910 1632.99 ;
    END
  END Vcc_wl_set
  PIN Vbias
    DIRECTION INOUT ;
    USE SIGNAL ;
    PORT
      LAYER met3 ;
        RECT 0 1672.49 20 1673.79 ;
    END
  END Vbias
  PIN Vcc_wl_reset
    DIRECTION INOUT ;
    USE SIGNAL ;
    PORT
      LAYER met3 ;
        RECT 1890 1713.29 1910 1714.59 ;
    END
  END Vcc_wl_reset
  PIN Vcc_set
    DIRECTION INOUT ;
    USE SIGNAL ;
    PORT
      LAYER met3 ;
        RECT 0 1754.09 20 1755.39 ;
    END
  END Vcc_set
  PIN VCC_SNEAK
    DIRECTION INOUT ;
    USE SIGNAL ;
    PORT
      LAYER met3 ;
        RECT 0 1835.69 20 1836.99 ;
    END
  END VCC_SNEAK
  PIN dc_bias
    DIRECTION INOUT ;
    USE SIGNAL ;
    PORT
      LAYER met3 ;
        RECT 1890 1794.89 1910 1796.19 ;
    END
  END dc_bias
  OBS
    LAYER li1 ;
      RECT 0 0 1910 2010.14 ;
    LAYER met1 ;
      RECT 0 0 1910 2010.14 ;
    LAYER met2 ;
      RECT 0 0 1910 2010.14 ;
    LAYER met3 ;
      RECT 0 0 1910 2010.14 ;
    LAYER met4 ;
      RECT 491.305 1312.925 689.2 1405.225 ;
  END
END sky130_bmlabs_reram__cim32x32

END LIBRARY
